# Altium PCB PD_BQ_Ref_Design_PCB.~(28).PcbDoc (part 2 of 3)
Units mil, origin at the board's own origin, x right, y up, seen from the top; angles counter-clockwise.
Board outline 2300 x 3400 mil, 4 copper layers (Top Layer, Signal Layer 1, Signal Layer 2, Bottom Layer), stack 61.2 mil thick; 124 components, 53 nets, 359 pads, 494 vias.
Unrouted connection lines stored in the file: 227.

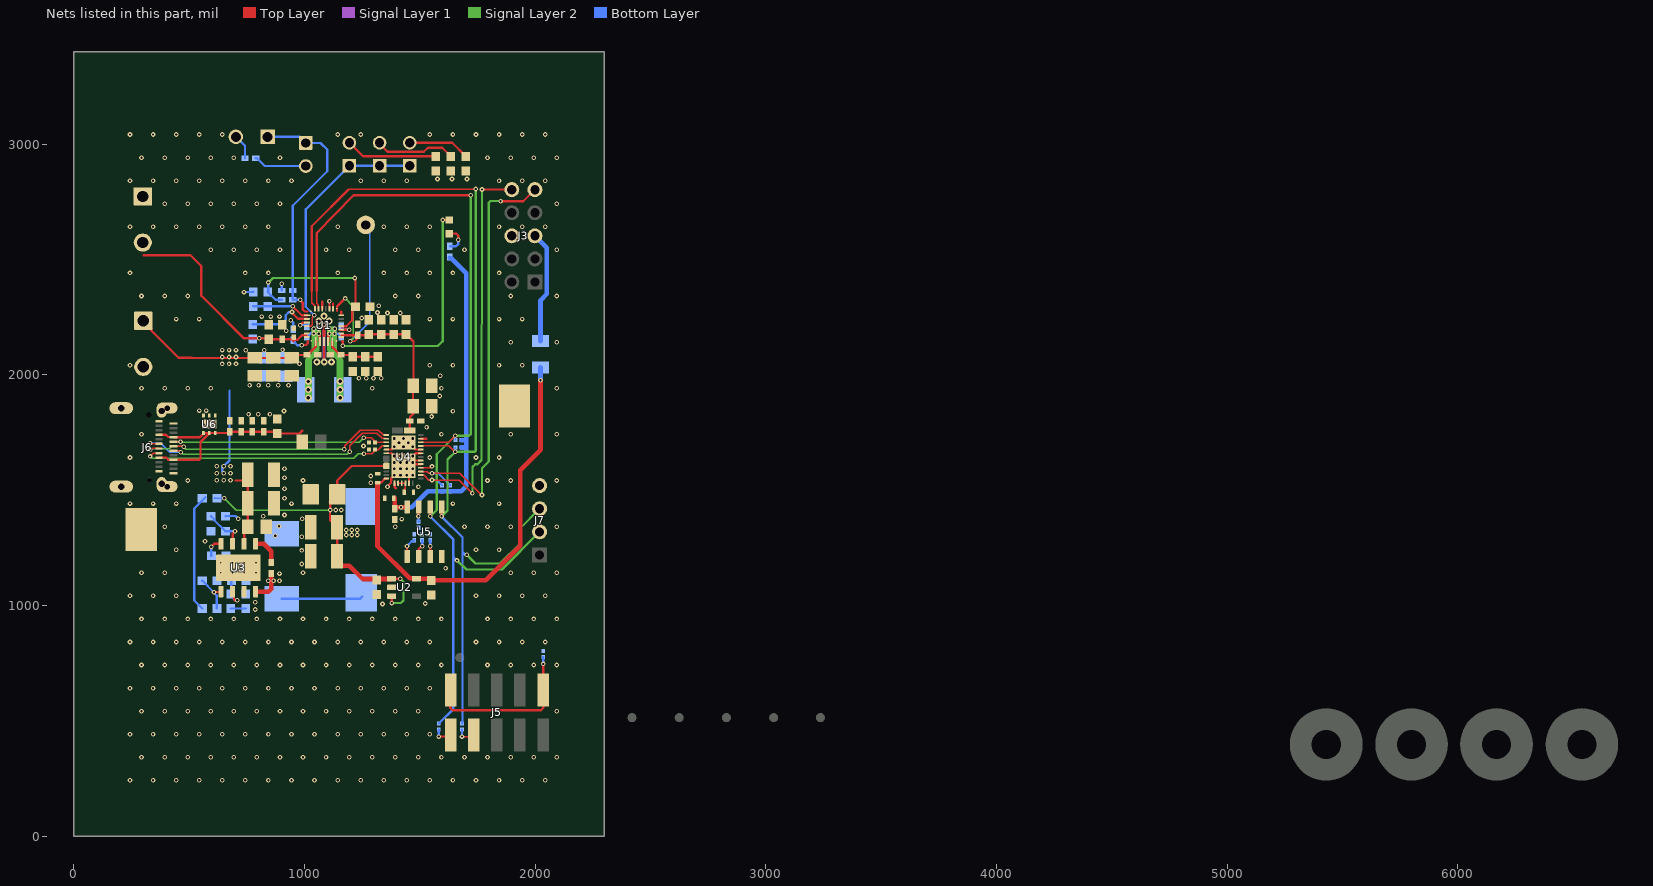
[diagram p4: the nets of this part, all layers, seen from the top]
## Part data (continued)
LOGO5: library part CMP-0074837-1, "IEC 61010-1 Hot Surface Warning"
NT1: library part CMP-0078142-3, "Single point connection between nets.", Manufacturer=N/A
R1: library part CMP-0022736-4, "RES, 100, 1%, 0.1 W, 0603", Manufacturer=Yageo, Power_W=100mW, Supplier Part Number 1=311-100HRCT-ND, TempCo="100 ppm/C", Tolerance_%=1%, Value2=0.1W, Value_Code=100R, ValueDisplayed=100
R2: library part CMP-0026232-2, "RES, 2.21 k, 1%, 0.063 W, AEC-Q200 Grade 0, 0402", Manufacturer=Vishay-Dale, Power_W=63mW, Supplier Part Number 1=541-2.21KLCT-ND, TempCo="100 ppm/C", Tolerance_%=1%, Value2=0.063W, Value_Code=2k21, ValueDisplayed=2.21k
R3: library part CMP-0026464-2, "RES, 5.23 k, 1%, 0.063 W, AEC-Q200 Grade 0, 0402", Manufacturer=Vishay-Dale, PartNumber=CRCW04025K23FKED, Power_W=63mW, Supplier Part Number 1=541-5.23KLCT-ND, TempCo="100 ppm/C", Tolerance_%=1%, Value2=0.063W, Value_Code=5k23, ValueDisplayed=5.23k
R4: library part CMP-0022788-4, "RES, 137 k, 1%, 0.1 W, 0603", Manufacturer=Yageo, Power_W=100mW, Supplier Part Number 1=311-137KHRCT-ND, TempCo="100 ppm/C", Tolerance_%=1%, Value2=0.1W, Value_Code=137k
R5: library part CMP-0026284-2, "RES, 30.1 k, 1%, 0.063 W, AEC-Q200 Grade 0, 0402", Manufacturer=Vishay-Dale, PartNumber=CRCW040230K1FKED, Power_W=63mW, Supplier Part Number 1=541-30.1KLCT-ND, TempCo="100 ppm/C", Tolerance_%=1%, Value2=0.063W, Value_Code=30k1, ValueDisplayed=30.1k
R6: library part CMP-0022735-5, "RES, 100 k, 1%, 0.1 W, 0603", Manufacturer=Yageo, Power_W=100mW, Supplier Part Number 1=311-100KHRCT-ND, TempCo="100 ppm/C", Tolerance_%=1%, Value2=0.1W, Value_Code=100k
R7: library part CMP-0025958-3, "RES, 10.0 k, 1%, 0.063 W, AEC-Q200 Grade 0, 0402", Manufacturer=Vishay-Dale, PartNumber=CRCW040210K0FKED, Power_W=63mW, Supplier Part Number 1=541-10.0KLCT-ND, TempCo="100 ppm/C", Tolerance_%=1%, Value2=0.063W, Value_Code=10k0, ValueDisplayed=10.0k
R8: library part CMP-0023246-5, "RES, 6.04 k, 1%, 0.1 W, 0603", Manufacturer=Yageo, Power_W=100mW, Supplier Part Number 1=311-6.04KHRCT-ND, TempCo="100 ppm/C", Tolerance_%=1%, Value2=0.1W, Value_Code=6k04, ValueDisplayed=6.04k
R9: library part CMP-0022000-4, "RES, 10.5 k, 1%, 0.1 W, AEC-Q200 Grade 0, 0603", Manufacturer=Vishay-Dale, Power_W=100mW, Supplier Part Number 1=541-10.5KHCT-ND, TempCo="100 ppm/C", Tolerance_%=1%, Value2=0.1W, Value_Code=10k5, ValueDisplayed=10.5k
R10: library part CMP-0022089-4, "RES, 17.4 k, 1%, 0.1 W, AEC-Q200 Grade 0, 0603", Manufacturer=Vishay-Dale, Power_W=100mW, Supplier Part Number 1=541-17.4KHCT-ND, TempCo="100 ppm/C", Tolerance_%=1%, Value2=0.1W, Value_Code=17k4, ValueDisplayed=17.4k
R11: library part CMP-0017299-3, "RES, 10.0, 1%, 0.25 W, AEC-Q200 Grade 0, 1206", Manufacturer=Panasonic, Power_W=250mW, Supplier Part Number 1=P10.0FCT-ND, TempCo="100 ppm/C", Tolerance_%=1%, Value2=0.25W, Value_Code=10R0, ValueDisplayed=10.0
R12: library part CMP-0022483-4, "RES, 51.1, 1%, 0.1 W, AEC-Q200 Grade 0, 0603", Manufacturer=Vishay-Dale, Power_W=100mW, Supplier Part Number 1=541-51.1HCT-ND, TempCo="100 ppm/C", Tolerance_%=1%, Value2=0.1W, Value_Code=51R1, ValueDisplayed=51.1
R13: library part CMP-0022546-4, "RES, 665 k, 1%, 0.1 W, AEC-Q200 Grade 0, 0603", Manufacturer=Vishay-Dale, Power_W=100mW, Supplier Part Number 1=541-665KHCT-ND, TempCo="100 ppm/C", Tolerance_%=1%, Value2=0.1W, Value_Code=665k
R14: library part CMP-0021999-4, "RES, 10.2 k, 1%, 0.1 W, AEC-Q200 Grade 0, 0603", Manufacturer=Vishay-Dale, Power_W=100mW, Supplier Part Number 1=541-10.2KHCT-ND, TempCo="100 ppm/C", Tolerance_%=1%, Value2=0.1W, Value_Code=10k2, ValueDisplayed=10.2k
R15: library part CMP-0022036-4, "RES, 130 k, 1%, 0.1 W, AEC-Q200 Grade 0, 0603", Manufacturer=Vishay-Dale, Power_W=100mW, Supplier Part Number 1=541-130KHCT-ND, TempCo="100 ppm/C", Tolerance_%=1%, Value2=0.1W, Value_Code=130k
R16: library part CMP-0022137-4, "RES, 1.96 k, 1%, 0.1 W, AEC-Q200 Grade 0, 0603", Manufacturer=Vishay-Dale, Power_W=100mW, Supplier Part Number 1=541-1.96KHCT-ND, TempCo="100 ppm/C", Tolerance_%=1%, Value2=0.1W, Value_Code=1k96, ValueDisplayed=1.96k
R17: library part CMP-0022360-4, "RES, 37.4 k, 1%, 0.1 W, AEC-Q200 Grade 0, 0603", Manufacturer=Vishay-Dale, Power_W=100mW, Supplier Part Number 1=541-37.4KHCT-ND, TempCo="100 ppm/C", Tolerance_%=1%, Value2=0.1W, Value_Code=37k4, ValueDisplayed=37.4k
R21 R22 R24 R25: library part CMP-0027272-3, "RES, 2.20 k, 1%, 0.05 W, 0201", Manufacturer=Vishay-Dale, Power_W=50mW, Supplier Part Number 1=541-2.20KAABCT-ND, TempCo="100 ppm/C", Tolerance_%=1%, Value2=0.05W, Value_Code=2k20, ValueDisplayed=2.20k
R26 R27 R29: library part CMP-0027008-4, "RES, 0, 5%, 0.05 W, 0201", Manufacturer=Vishay-Dale, Power_W=50mW, Supplier Part Number 1=72M6743, TempCo=ppm/C, Tolerance_%=5%, Value2=0.05W, Value_Code=0000, ValueDisplayed=0
R28 R30 R31 R32: library part CMP-0027262-3, "RES, 10.0 k, 1%, 0.05 W, 0201", Manufacturer=Vishay-Dale, Power_W=50mW, Supplier Part Number 1=541-10.0KAABCT-ND, TempCo="100 ppm/C", Tolerance_%=1%, Value2=0.05W, Value_Code=10k0, ValueDisplayed=10.0k
SH-J1 SH-J2: library part CMP-0003623-1, "Shunt, 100mil, Gold plated, Black", Alternate Manufacturer=3M, Alternate PartNumber=969102-0000-DA, Manufacturer=Samtec, Supplier Part Number 1=SNT-100-BK-G-ND
TP1: library part CMP-0055137-1, "Test Point, Miniature, Red, TH", Color=Red, Manufacturer=Keystone, Supplier Part Number 1=36-5000-ND
TP2 TP3: library part CMP-0055153-1, "Test Point, Compact, SMT", Manufacturer=Keystone, Supplier Part Number 1=36-5016TR-ND
U1: library part CMP-0088656-1, "BQ2579x HotRod", Manufacturer="Texas Instruments", Operating Temperature Range=to
U2: library part CMP-0074640-3, "500-mA, Low IQ, Small Size, Low Dropout Regulator, DBV0005A (SOT-23-5)", Alternate Manufacturer="Texas Instruments"
U3: library part CMP-0067056-2, "3.5V to 28V Input, 5A, 570kHz Step-Down Converter with Eco-mode, DDA0008E (SOIC-8)", Alternate Manufacturer="Texas Instruments", Alternate PartNumber=TPS54531DDA
U4: library part CMP-0090338-5, "USB Type-C and USB PD Controller with Integrated Power Switches Optimized for Power Applications", Manufacturer="Texas Instruments", Max Supply Voltage=22V, Min Supply Voltage=3V, Operating Temperature Range="-40°C to +125°C"
U5: library part CMP-0005314-2, "256 kb I2C CMOS Serial EEPROM, SOIC-8", Manufacturer="ON Semiconductor", Supplier Part Number 1=CAT24C256WI-G-ND
U6: library part CMP-0077834-1, "22-V Precision Surge Protection Clamp, DRV0006A (WSON-6)", Alternate Manufacturer="Texas Instruments"
ZZ1: library part CMP-0003616-3

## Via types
v1: diameter 20, hole 10, Top Layer to Bottom Layer, tented both sides, 445 vias
v2: diameter 23.62, hole 11.81, Top Layer to Bottom Layer, 24 vias
v3: diameter 30, hole 15, Top Layer to Bottom Layer, tented both sides, 12 vias
v4: diameter 19.68, hole 7.87, Top Layer to Bottom Layer, tented both sides, 10 vias
v5: diameter 20, hole 10, Top Layer to Bottom Layer, 3 vias

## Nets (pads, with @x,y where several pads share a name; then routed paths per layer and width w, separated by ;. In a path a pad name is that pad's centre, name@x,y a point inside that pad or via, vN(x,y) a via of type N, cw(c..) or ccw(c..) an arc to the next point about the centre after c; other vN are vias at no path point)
AGND: C22.2 J3.6 J4.2 NT1.2 R5.1 R6.1 R7.1 R8.1 R9.1 R10.1 U1.10 U1.11 U1.13 | length 298.5
  Top Layer w10: 1076.77,2316.93 1076.89,2316.81 U1.13@1076.89,2285.33 ; 1108.27,2307.09 1108.27,2285.45 U1.11@1108.39,2285.33 ; 1124.02,2309.06 1124.13,2308.94 U1.10@1124.13,2285.33
  Bottom Layer w10: J4.2@702.76,3031.5 742.13,2992.13 R7.1@742.13,2938.98 ; v1(738.19,2358.27) 776.76,2358.27 R6.1@777.74,2359.25 ; v1(901.57,2393.7) 901.57,2365.28 R5.1@901.69,2365.16 ; v1(940.94,2236.22) 951.89,2225.28 C22.2@951.89,2196.85
  other v1: 1108.27,2318.9 1576.77,2848.43 1639.76,2848.43 1704.72,2848.43
BAT: C19.1 C20.1 C21.1 J2.2 R1.1 U1.22 U1.23 | length 977.6
  Top Layer w10: 303.15,2518.11 505.51,2518.11 553.15,2470.47 553.15,2342.52 738.19,2157.48 v1(804.75,2157.48) 840.67,2157.48 C21.1@844.61,2153.54 C20.1@903.66,2153.54 946.97,2153.54 952.87,2147.64 ; 952.87,2145.67 952.87,2147.64 ; 1008.98,2171.26 989.29,2171.26 969.72,2151.69 956.93,2151.69 952.87,2147.64
  Bottom Layer w10: R1.1@775.59,2155.51 777.56,2153.54 781.5,2157.48 v1(804.75,2157.48)
C_CC1: C42.1 J6.A5 U4.28 | length 942.2
  Top Layer w6: J6.A5@432.09,1709.65 432.58,1709.15 462.11,1709.15 v1(462.6,1708.66) ; v1(1256.7,1726.38) 1289.27,1726.38 1306.3,1709.35 C42.1@1306.3,1706.69 1354.95,1706.69 U4.28@1355.13,1706.87
  Signal Layer 2 w6: v1(462.6,1708.66) 464.57,1706.69 1237.01,1706.69 v1(1256.7,1726.38)
C_CC2: C41.1 J6.B5 U4.29 | length 1095.8
  Top Layer w6: v1(330.71,1645.67) 345.47,1660.43 J6.B5@369.09,1660.43 ; v1(1257.87,1657.48) 1291.24,1657.48 1306.3,1672.54 C41.1@1306.3,1675.2 1320.87,1675.2 1336.8,1691.13 U4.29@1355.13,1691.13
  Signal Layer 2 w6: v1(330.71,1645.67) 333.35,1645.67 341.22,1637.8 1214.57,1637.8 1234.25,1657.48 v1(1257.87,1657.48)
C_USB_N: J6.A7 J6.B7 U4.27 | length 1182
  Top Layer w6: v1(330.71,1702.76) 333.66,1699.8 J6.B7@369.09,1699.8 ; J6.A7@432.09,1670.28 457.68,1670.28 v1(463.52,1664.43) ; v1(1196.85,1665.35) 1196.85,1692.91 1250.81,1746.87 1314.15,1746.87 1337.46,1723.56 1354.19,1723.56 U4.27@1355.13,1722.62
  Signal Layer 2 w6: v1(463.52,1664.43) 465.12,1664.43 474.04,1655.51 1186.34,1655.51 v1@1196.51,1665.69
  Bottom Layer w6: v1(330.71,1702.76) 377.95,1702.76 416.28,1664.43 v1(463.52,1664.43) ; v1@1196.18,1665.35 v1(1196.85,1665.35)
C_USB_P: J6.A6 J6.B6 U4.26 | length 1175.4
  Top Layer w6: v1(330.71,1674.76) 334.5,1674.76 339.86,1680.12 J6.B6@369.09,1680.12 ; J6.A6@432.09,1689.96 469.64,1689.96 472.59,1687.01 v1(476.38,1687.01) ; v1(1173.23,1677.17) 1173.77,1677.71 1173.77,1691.49 1242.13,1759.84 1320.87,1759.84 1341.4,1739.31 1354.19,1739.31 U4.26@1355.13,1738.37
  Signal Layer 2 w6: v1(330.71,1674.76) 334.5,1674.76 338.88,1679.13 413.39,1679.13 424.21,1689.96 465.86,1689.96 466.14,1689.69 473.7,1689.69 v1(476.38,1687.01) ; v1@474.9,1688.48 486.22,1677.17 v1(1173.23,1677.17)
GND: C2.1 C3.1 C4.1 C5.1 C6.2 C8.1 C9.1 C10.1 C11.2 C12.2 C13.2 C14.2 C15.2 C16.2 C17.2 C18.2 C19.2 C20.2 C21.2 C23.1 C24.1 C26.2 C27.2 C28.2 C29.2 C30.2 C31.2 C33.2 C34.2 C35.2 C36.2 C37.2 C38.2 C39.2 C40.2 C41.2 C42.2 C43.2 C44.2 C45.1 C46.1 C47.1 C48.1 D2.2 J1.2 J2.1 J6.A1 J6.A12 J6.B1 J6.B12 J6.S1 J6.S2 J6.S3 J6.S4 J7.4 NT1.1 R15.1 R16.1 R17.1 R28.1 R29.1 R30.1 R31.1 R32.1 TP2.1 TP3.1 U1.27 U2.2 U3.7 U3.9@713.58,1163.11 U4.5 U4.10 U4.11 U4.12 U4.14 U4.18 U4.31 U4.39 U5.4 U6.1 U6.2 U6.3 U6.7@587.6,1785.43 | length 894.8
  Top Layer w6: U4.10@1504.73,1596.64 1547.42,1596.64 v1(1553.15,1602.36)
  Top Layer w8: U4.31@1355.13,1659.63 1377.57,1659.63
  Top Layer w10: 1084.76,2171.26 U1.27@1084.76,2143.6 1084.76,2055.12 v3(1085.75,2055.12) ; v1(1360.24,1513.78) 1360.24,1516.49 1375.56,1531.81 1375.56,1541.09 1376.94,1542.47 1376.94,1551.52 1429.93,1604.51 U4.39@1429.93,1605.89 ; 1377.57,1659.63 U4.39@1429.93,1607.27 ; U4.39@1443.51,1592.31 U4.39@1429.93,1605.89 ; U4.39@1443.51,1619.47 U4.39@1429.93,1605.89 ; U4.39@1451.48,1628.82 1482.29,1659.63 U4.14@1504.73,1659.63 ; U4.39@1452.17,1628.13 U4.12@1504.73,1628.13 U4.39@1470.09,1628.13 ; U4.5@1453.55,1529.71 U4.39@1453.55,1582.27 ; U4.39@1470.09,1612.39 U4.11@1504.73,1612.39 ; U4.18@1504.73,1722.62 1527.74,1722.62
  Top Layer w15: 1084.76,2171.26 v1@1084.76,2216.72
  Signal Layer 1 w15: v1(1084.76,2216.75) 1084.88,2216.63 1084.88,2055.98 v3(1085.75,2055.12)
  other v1: 243.83,241.2 343.83,241.2 443.83,241.2 543.83,241.2 643.83,241.2 743.83,241.2 843.83,241.2 943.83,241.2 1043.83,241.2 1143.83,241.2 1243.83,241.2 1343.83,241.2 1443.83,241.2 1543.83,241.2 1643.83,241.2 1743.83,241.2 1843.83,241.2 1943.83,241.2 2043.83,241.2 293.83,341.2 393.83,341.2 493.83,341.2 593.83,341.2 693.83,341.2 793.83,341.2 893.83,341.2 993.83,341.2 1093.83,341.2 1193.83,341.2 1293.83,341.2 1393.83,341.2 1493.83,341.2 1593.83,341.2 1693.83,341.2 1793.83,341.2 1893.83,341.2 1993.83,341.2 2093.83,341.2 243.83,441.2 343.83,441.2 443.83,441.2 543.83,441.2 643.83,441.2 743.83,441.2 843.83,441.2 943.83,441.2 1043.83,441.2 1143.83,441.2 1243.83,441.2 1343.83,441.2 1443.83,441.2 1543.83,441.2 293.83,541.2 393.83,541.2 493.83,541.2 593.83,541.2 693.83,541.2 793.83,541.2 893.83,541.2 993.83,541.2 1093.83,541.2 1193.83,541.2 1293.83,541.2 1393.83,541.2 1493.83,541.2 2093.83,541.2 243.83,641.2 343.83,641.2 443.83,641.2 543.83,641.2 643.83,641.2 743.83,641.2 843.83,641.2 943.83,641.2 1043.83,641.2 1143.83,641.2 1243.83,641.2 1343.83,641.2 1443.83,641.2 1543.83,641.2 293.83,741.2 393.83,741.2 493.83,741.2 593.83,741.2 693.83,741.2 793.83,741.2 893.83,741.2 993.83,741.2 1093.83,741.2 1193.83,741.2 1293.83,741.2 1393.83,741.2 1493.83,741.2 1593.83,741.2 1793.83,741.2 1893.83,741.2 1993.83,741.2 2093.83,741.2 243.83,841.2 343.83,841.2 443.83,841.2 543.83,841.2 643.83,841.2 743.83,841.2 843.83,841.2 943.83,841.2 1043.83,841.2 1143.83,841.2 1243.83,841.2 1343.83,841.2 1443.83,841.2 1543.83,841.2 1743.83,841.2 1843.83,841.2 1943.83,841.2 2043.83,841.2 293.83,941.2 393.83,941.2 493.83,941.2 593.83,941.2 693.83,941.2 793.83,941.2 893.83,941.2 993.83,941.2 1093.83,941.2 1193.83,941.2 1293.83,941.2 1393.83,941.2 1493.83,941.2 1593.83,941.2 1793.83,941.2 1893.83,941.2 1993.83,941.2 2093.83,941.2 787.4,982.28 1338.58,1005.91 1523.31,1007.87 787.4,1013.78 243.83,1041.2 343.83,1041.2 443.83,1041.2 1743.83,1041.2 1843.83,1041.2 1943.83,1041.2 2043.83,1041.2 293.83,1141.2 393.83,1141.2 993.83,1141.2 1893.83,1141.2 1993.83,1141.2 2093.83,1141.2 1611.89,1161.42 988.19,1179.13 988.19,1238.19 443.83,1241.2 1743.83,1241.2 1843.83,1241.2 568.9,1277.56 988.19,1297.24 874.02,1301.18 393.83,1341.2 1393.83,1341.2 1693.83,1341.2 1793.83,1341.2 1893.83,1341.2 2093.83,1341.2 889.76,1342.52 1421.26,1374.02 990.16,1375.98 820.87,1385.83 913.39,1391.73 243.83,1441.2 343.83,1441.2 443.83,1441.2 943.83,1441.2 1643.83,1441.2 1843.83,1441.2 913.39,1464.57 913.39,1505.91 1494.09,1513.78 1287.4,1531.5 493.83,1541.2 993.83,1541.2 1793.83,1541.2 1893.83,1541.2 2093.83,1541.2 913.39,1553.15 1287.4,1561.02 913.39,1592.52 243.83,1641.2 1543.83,1641.2 1743.83,1641.2 1843.83,1641.2 1255.91,1690.94 293.83,1741.2 1593.83,1741.2 1893.83,1741.2 2093.83,1741.2 1529.53,1771.65 1551.18,1818.9 757.87,1828.74 799.21,1828.74 850.39,1828.74 1643.83,1841.2 911.42,1842.52 543.31,1844.49 574.8,1844.49 1586.61,1907.48 293.83,1941.2 393.83,1941.2 493.83,1941.2 593.83,1941.2 1293.83,1941.2 1593.83,1941.2 2093.83,1941.2 762.09,1954.72 801.18,1954.72 842.52,1954.72 885.83,1954.72 931.1,1954.72 1236.22,1984.25 1267.72,1984.25 1299.21,1984.25 1332.68,1984.25 1588.58,1996.06 243.83,2041.2 1543.83,2041.2 1643.83,2041.2 1843.83,2041.2 1943.83,2041.2 1893.83,2141.2 2093.83,2141.2 921.26,2190.94 443.83,2241.2 543.83,2241.2 1543.83,2241.2 1643.83,2241.2 1843.83,2241.2 1943.83,2241.2 1248.03,2246.06 814.96,2251.97 854.33,2251.97 891.73,2251.97 1360.24,2267.72 1415.35,2267.72 1316.93,2269.69 1322.83,2299.21 293.83,2341.2 393.83,2341.2 493.83,2341.2 1393.83,2341.2 1493.83,2341.2 1893.83,2341.2 2093.83,2341.2 243.83,2441.2 743.83,2441.2 843.83,2441.2 1143.83,2441.2 1343.83,2441.2 1443.83,2441.2 1543.83,2441.2 1643.83,2441.2 1843.83,2441.2 593.83,2541.2 693.83,2541.2 793.83,2541.2 893.83,2541.2 1093.83,2541.2 1193.83,2541.2 1393.83,2541.2 1493.83,2541.2 1693.83,2541.2 2093.83,2541.2 243.83,2641.2 343.83,2641.2 443.83,2641.2 543.83,2641.2 643.83,2641.2 743.83,2641.2 843.83,2641.2 1143.83,2641.2 1343.83,2641.2 1443.83,2641.2 1543.83,2641.2 1843.83,2641.2 1943.83,2641.2 2043.83,2641.2 393.83,2741.2 493.83,2741.2 593.83,2741.2 693.83,2741.2 793.83,2741.2 893.83,2741.2 2093.83,2741.2 243.83,2841.2 343.83,2841.2 443.83,2841.2 543.83,2841.2 643.83,2841.2 743.83,2841.2 843.83,2841.2 943.83,2841.2 1243.83,2841.2 1343.83,2841.2 1443.83,2841.2 1843.83,2841.2 1943.83,2841.2 2043.83,2841.2 293.83,2941.2 393.83,2941.2 493.83,2941.2 593.83,2941.2 693.83,2941.2 893.83,2941.2 1793.83,2941.2 1893.83,2941.2 1993.83,2941.2 2093.83,2941.2 243.83,3041.2 343.83,3041.2 443.83,3041.2 543.83,3041.2 643.83,3041.2 1143.83,3041.2 1243.83,3041.2 1543.83,3041.2 1643.83,3041.2 1743.83,3041.2 1843.83,3041.2 1943.83,3041.2 2043.83,3041.2
  other v2: 1389.77,1564.55 1416.54,1564.55 1443.32,1564.55 1470.09,1564.55 1389.77,1592.11 1416.54,1592.11 1443.32,1592.11 1470.09,1592.11 1389.77,1619.67 1416.54,1619.67 1443.32,1619.67 1470.09,1619.67 1389.77,1647.23 1416.54,1647.23 1443.32,1647.23 1470.09,1647.23
  other v3: 1054.25,2055.12 1117.24,2055.12 1062.11,2232.27 1107.4,2232.28 1084.75,2254.14
  other v4: 636.81,1141.46 687.99,1141.46 739.17,1141.46 790.35,1141.46 636.81,1184.76 687.99,1184.76 739.17,1184.76 790.35,1184.76 565.94,1785.43 609.25,1785.43
I2C1_SCL: J3.9 R21.1 U4.9 | length 1911.4
  Top Layer w6: U4.9@1504.73,1580.89 1505.67,1579.95 1532.36,1579.95 1539.48,1572.83 v1(1553.15,1572.83) 1673.23,1572.83 1768.7,1477.36 v5@1769.69,1476.38
  Top Layer w10: v5(1850.39,2751.97) 1948.82,2751.97 J3.9@1999.02,2802.17
  Signal Layer 2 w10: v5(1769.69,1478.35) 1769.69,1594.08 1799.21,1623.61 1799.21,2744.84 1807.09,2752.72 1849.65,2752.72 v5(1850.39,2751.97)
  Bottom Layer w10: v1(1553.15,1572.83) 1579.92,1572.83 R21.1@1631.89,1520.87
I2C1_SDA: J3.10 R22.1 U4.8 | length 1783.2
  Top Layer w6: U4.8@1504.73,1565.14 1505.67,1564.2 1518.47,1564.2 1539.37,1543.31 v1(1553.15,1543.31) 1671.26,1543.31 v1(1728.35,1486.22) v1@1728.35,1484.25
  Top Layer w10: v5(1769.69,2803.15) J3.10@1899.02,2802.17
  Signal Layer 2 w10: v1(1728.35,1486.22) 1728.35,1600.39 1740.16,1612.2 1750,1612.2 1767.72,1629.92 1769.69,2805.12 v5(1769.69,2803.15)
  Bottom Layer w10: v1(1553.15,1543.31) 1574.02,1543.31 R22.1@1596.46,1520.87
I2C_SCL: J7.2 R24.2 R26.1 U1.14 U4.17 U5.6 | length 4218
  Top Layer w6: 1053.15,2364.17 1053.15,2309.06 1060.2,2302 1060.2,2286.27 U1.14@1061.14,2285.33 ; U4.17@1504.73,1706.87 1624.95,1706.87 v1(1653.54,1735.47)
  Top Layer w10: 1053.15,2364.17 1053.15,2614.17 1212.6,2777.56 v1(1720.47,2777.56) ; v1(1545.28,1385.83) U5.6@1545.28,1426.7
  Signal Layer 2 w10: v1(1545.28,1385.83) 1573.15,1413.7 1573.15,1655.08 v1(1653.54,1735.47) 1713.82,1735.47 1720.47,1742.13 v1(1720.47,2777.56) ; v1(1661.42,1194.88) 1702.76,1155.51 1856.3,1155.51 J7.2@2019.69,1318.9
  Bottom Layer w6: v1(1653.54,1735.47) 1653.54,1717.32 R24.2@1654.33,1716.54
  Bottom Layer w10: v1(1545.28,1385.83) 1645.67,1285.43 1645.67,1208.66 ; R26.1@1582.68,487.4 1582.68,488.19 1585.94,491.46 1586.03,491.46 1645.67,551.09 1645.67,1208.66 ; v1(1661.42,1194.88) 1647.64,1208.66 1645.67,1208.66
I2C_SDA: J7.3 R25.2 R27.1 U1.15 U4.16 U5.5 | length 4321.3
  Top Layer w6: 1031.5,2364.17 1031.5,2311.02 1044.46,2298.06 1044.46,2286.27 U1.15@1045.39,2285.33 ; U4.16@1504.73,1691.13 1625.8,1691.13 1651.58,1665.35 v1(1653.54,1665.35)
  Top Layer w10: 1031.5,2364.17 1031.5,2643.7 1190.94,2803.15 ; 1188.98,2803.15 v1@1740.16,2805.12 ; v1(1594.49,1385.83) U5.5@1594.49,1426.7
  Signal Layer 2 w10: v1(1594.49,1385.83) 1620.08,1411.42 1620.08,1631.89 v1(1653.54,1665.35) 1738.19,1665.35 1742.13,1669.29 v1(1742.13,2805.12) ; v1(1704.33,1218.9) 1742.13,1181.1 1848.43,1181.1 1933.07,1265.75 1933.07,1332.28 J7.3@2019.69,1418.9
  Bottom Layer w6: v1(1653.54,1665.35) 1653.54,1684.25 R25.2@1654.33,1685.04
  Bottom Layer w10: v1(1594.49,1385.83) 1685.04,1295.28 1685.04,1232.28 ; R27.1@1683.07,487.4 1685.04,489.37 1685.04,1232.28 ; v1(1704.33,1218.9) 1698.43,1218.9 1685.04,1232.28
ILIM_HIZ: R4.1 R6.2 U1.17 | length 250.9
  Top Layer w10: v1(948.82,2297.24) 988.28,2257.77 U1.17@1011.93,2257.77
  Bottom Layer w10: R6.2@777.74,2296.26 778.73,2297.24 938.5,2297.24 v1(948.82,2297.24)
LDO_1V5: C37.1 U4.2 U4.3 U4.4 | length 83
  Top Layer w6: U4.2@1406.31,1529.71 U4.3@1422.06,1529.71 U4.4@1437.8,1529.71 1437.8,1508.67 1433.07,1503.94 1433.07,1480.63 C37.1@1432.76,1480.32
LDO_3V3: C36.1 C43.1 R2.2 R21.2 R22.2 R24.1 R25.1 U4.1 U5.8 | length 1507.2
  Top Layer w10: U4.1@1390.56,1529.71 1391.62,1528.65 1391.62,1511.92 1395.67,1507.87
  Top Layer w20: C43.1@1391.73,1419.29 1391.73,1423.23 C43.1@1393.54,1425.04 ; C36.1@1391.73,1465.4 1391.73,1425.04 C43.1@1393.54,1425.04 ; U5.8@1444.88,1427.09 1443.62,1425.83 v1(1418.59,1425.83) 1417.96,1425.2 1405.26,1425.2 1405.1,1425.04 C43.1@1393.54,1425.04
  Bottom Layer w20: v1@1419.29,1425.83 1465.2,1425.83 1534.25,1494.88 1604.33,1494.88 1633.86,1494.88 1663.39,1494.88 1679.92,1494.88 1700.79,1515.75 1700.79,1684.54 ; R2.2@1629.92,2506.89 1632.72,2504.09 1635.67,2504.09 1700.79,2438.98 1700.79,1717.11 ; R25.1@1680.31,1685.04 1680.81,1684.54 1700.79,1684.54 ; R24.1@1680.31,1716.54 1700.21,1716.54 1700.79,1717.11 ; 1700.79,1684.54 1700.79,1717.11
NetC1_1: C1.1 U1.4 | length 76.9
  Top Layer w10: U1.4@1159.57,2194.78 1193.92,2194.78 v1(1194.02,2194.88)
  Bottom Layer w10: C1.1@1160.55,2210.63 1160.55,2206.69 1172.46,2194.78 1193.92,2194.78 v1(1194.02,2194.88)
NetC1_2: C1.2 L1.1 U1.28 | length 640.5
  Top Layer w10: U1.28@1102.48,2143.6 1103.54,2144.66 1103.54,2172.44 v1(1108.27,2177.17)
  Signal Layer 2 w20: 1154.65,2061.02 1130.25,2085.42 ; v1(1108.27,2177.17) 1108.27,2197.95 v1(1107.4,2198.82) v1(1131.02,2198.82) 1129.92,2197.72 v1(1129.92,2177.17) ; v1(1108.27,2177.17) v1(1129.92,2177.17) ; v1(1108.27,2177.17) 1108.27,2109.17 1107.38,2108.29 1130.25,2085.42 ; v1(1129.92,2177.17) 1130.25,2176.84 1130.25,2085.42
  Signal Layer 2 w30: v3(1154.65,1899.61) 1154.65,2061.02
  Bottom Layer w10: v1(1129.92,2177.17) 1146.77,2177.17 C1.2@1160.55,2163.39
  Bottom Layer w20: v1@1107.4,2178.93 1108.27,2178.07 v1(1108.27,2177.17) v1(1129.92,2177.17) 1129.92,2197.72 v1(1131.02,2198.82) v1(1107.4,2198.82) v1@1107.4,2178.93
  other v3: 1154.65,1935.04 1154.65,1970.64
NetC7_1: C7.1 U1.19 | length 77
  Top Layer w10: v1(981.42,2214.57) 993.13,2226.28 U1.19@1011.54,2226.28
  Bottom Layer w10: v1(981.42,2214.57) 982.92,2216.07 1005.5,2216.07 C7.1@1010.94,2210.63 ; C7.1@1006.18,2214.57 C7.1@1012.99,2221.38
NetC7_2: C7.2 L1.2 U1.26 | length 624.4
  Top Layer w10: v1(1062.13,2177.73) 1062.13,2176.43 1065.98,2172.57 1065.98,2144.66 U1.26@1067.05,2143.6
  Signal Layer 2 w20: 1016.85,2062.24 1040.47,2085.86 v1(1040.47,2178.56) 1061.3,2178.56 v1(1062.13,2177.73) ; 1040.47,2092.52 1054.25,2106.3 1054.25,2169.86 v1(1062.13,2177.73) ; v1@1040.47,2179.54 v1(1040.47,2198.82) v1(1062.13,2198.82) v1(1062.13,2177.73)
  Signal Layer 2 w30: v3(1016.85,1899.61) v3(1016.85,1935.04) v3(1016.85,1970.5) 1016.85,2062.24
  Bottom Layer w10: C7.2@1010.94,2163.39 1026.69,2179.13 1027.27,2178.56 v1(1040.47,2178.56)
  Bottom Layer w20: v1(1040.47,2178.56) 1061.3,2178.56 v1(1062.13,2177.73) v1(1062.13,2198.82) v1(1040.47,2198.82) v1(1040.47,2178.56)
NetC22_1: C22.1 U1.24 | length 87.7
  Top Layer w10: v1(988.19,2127.95) 988.84,2128.6 1006.55,2128.6 1014.73,2136.78 1014.73,2144.71 1013.78,2145.67
  Bottom Layer w10: C22.1@951.89,2149.61 958.7,2142.8 958.7,2137.75 968.5,2127.95 v1(988.19,2127.95)
NetC25_1: C25.1 U3.1 | length 129.4
  Top Layer w20: U3.1@788.58,1266.46 824.09,1266.46 855.57,1234.98 C25.1@855.57,1185.58
NetC25_2: C25.2 D2.1 L2.1 U3.8 | length 493.1
  Top Layer w20: U3.8@788.58,1059.76 788.7,1059.76 789.41,1059.06 843.85,1059.06 855.57,1070.77 C25.2@855.57,1138.33
  Bottom Layer w10: D2.1@901.57,1028.8 1241.4,1028.8 L2.1@1250.98,1038.39
  other v1: 842.52,1106.3 866.14,1106.3 891.73,1106.3 891.73,1137.8
NetC32_1: C32.1 C34.1 U3.6 | length 164.6
  Top Layer w10: U3.6@688.58,1059.76 694.41,1053.94 694.41,1026.06 698.82,1021.65 v1(708.66,1021.65)
  Bottom Layer w10: C32.1@682.61,1049.21 C32.1@682.61,1047.75 ; C34.1@683.07,1106.3 683.07,1051.18 C32.1@681.1,1049.21 C32.1@682.61,1047.75 ; C32.1@683.81,1039.6 685.33,1045.12 C32.1@682.61,1047.75 ; v1(708.66,1021.65) 700.89,1021.65 682.61,1039.93 C32.1@682.61,1047.75
NetC32_2: C32.2 R17.2 | length 65.9
  Bottom Layer w10: C32.2@681.1,986.22 R17.2@747.05,986.22
NetC33_1: C33.1 U3.4 | length 86.7
  Top Layer w10: v1(596.46,1253.94) 608.98,1266.46 U3.4@638.58,1266.46
  Bottom Layer w10: C33.1@596.46,1214.57 v1(596.46,1253.94)
NetC44_1: C44.1 C45.2 C46.2 C47.2 C48.2 J6.A4 J6.A9 J6.B4 J6.B9 L3.1 U6.4 U6.5 U6.6 | length 961.1
  Top Layer w10: J6.B4@369.09,1640.75 399.84,1640.75 409.37,1631.22 431.77,1631.22 J6.A9@432.09,1630.91 447.21,1630.91 543.35,1630.91 549.21,1636.76 549.21,1708.66 583.74,1743.19 586.69,1743.19 587.6,1744.09 U6.5@587.6,1747.05 ; J6.B9@369.09,1739.17 399.84,1739.17 409.37,1729.65 431.77,1729.65 J6.A4@432.09,1729.33 547.24,1729.33 562.01,1744.09 U6.4@562.01,1747.05 583.74,1747.05 U6.5@587.6,1747.05 ; 991.5,1757.87 978.7,1745.08 C44.1@882.87,1745.08 875,1752.95 C48.2@823.82,1752.95 C47.2@774.61,1752.95 C46.2@725.39,1752.95 C45.2@676.18,1752.95 670.28,1747.05 U6.6@613.19,1747.05 U6.5@587.6,1747.05
NetD1_1: D1.1 R2.1 | length 119.8
  Top Layer w10: D1.1@1627.95,2611.22 1628.94,2612.2 1657.48,2612.2 1667.32,2602.36 v1(1667.32,2584.65)
  Bottom Layer w10: R2.1@1630.91,2557.09 1657.48,2557.09 1667.32,2566.93 v1(1667.32,2584.65)
NetJ3_5: J3.5 R11.1 | length 489.2
  Bottom Layer w20: J3.5@1999.02,2602.17 2050.83,2550.35 2050.83,2350.04 2023.62,2322.83 R11.1@2023.62,2145.67
NetJ5_1: J5.1 R26.2 | length 85
  Top Layer w10: v1(1582.68,431.1) 1627.5,431.1 J5.1@1634.47,438.07
  Bottom Layer w10: v1(1582.68,431.1) R26.2@1582.68,461.42
NetJ5_2: J5.2 J5.10 R29.2 | length 712.5
  Top Layer w10: J5.2@1634.47,632.95 1631.99,630.47 1631.99,555.02 1641.73,545.28 2025.59,545.28 2035.34,555.02 2035.34,632.08 J5.10@2034.47,632.95 2035.43,633.92 v1(2035.43,746.06)
  Bottom Layer w10: v1(2035.43,746.06) R29.2@2035.43,776.38
NetJ5_3: J5.3 R27.2 | length 84.6
  Top Layer w6: v1(1683.07,431.1) 1727.5,431.1 J5.3@1734.47,438.07
  Bottom Layer w10: v1(1683.07,431.1) R27.2@1683.07,461.42
NetJP1_2: JP1.2 R8.2 | length 398.4
  Top Layer w10: JP1.2@1194.88,3005.71 1253.74,2946.85 R8.2@1568.9,2946.85
NetJP2_2: JP2.2 R9.2 | length 350.8
  Top Layer w10: JP2.2@1325.79,3005.71 1325.79,3000.98 1360.59,2966.18 1517.56,2966.18 1535.63,2984.25 1597.44,2984.25 1633.86,2947.83 R9.2@1633.86,2946.85
NetJP3_2: JP3.2 R10.2 | length 267.1
  Top Layer w10: JP3.2@1456.69,3005.71 1640.94,3005.71 1698.82,2947.83 R10.2@1698.82,2946.85
NetJP4_2: JP4.2 R7.2 | length 230.7
  Bottom Layer w10: R7.2@789.37,2938.98 793.31,2938.98 827.56,2904.72 JP4.2@1005.91,2904.72
NetR1_2: R1.2 U1.18 | length 281.9
  Top Layer w10: v1(945.98,2271.65) 945.98,2268.58 971.79,2242.77 1010.2,2242.77 U1.18@1010.94,2242.03
  Bottom Layer w10: R1.2@775.59,2218.5 897.64,2218.5 919.29,2240.16 919.29,2257.77 919.24,2257.82 933.07,2271.65 v1(945.98,2271.65)
NetR12_1: R12.1 R14.2 | length 516.5
  Bottom Layer w10: R14.2@557.09,986.22 522.64,1020.67 522.64,1420.28 R12.1@570.87,1468.5
NetR13_1: R13.1 R15.2 U3.3 | length 192.6
  Top Layer w10: U3.3@688.58,1266.46 688.58,1310.63 v1(698.82,1320.87)
  Bottom Layer w10: R13.1@594.49,1386.81 595.47,1386.81 609.17,1373.11 609.17,1369.17 656.5,1321.85 R15.2@657.48,1321.85 658.46,1320.87 v1(698.82,1320.87)
NetR14_1: R14.1 R16.2 U3.5 | length 179
  Top Layer w10: v1(607.77,1057.09) 608.65,1057.96 636.78,1057.96 U3.5@638.58,1059.76
  Bottom Layer w10: R16.2@557.09,1106.3 558.07,1106.3 607.28,1057.09 v1(607.77,1057.09) 607.77,1054.38 620.08,1042.08 R14.1@620.08,986.22
NetR28_2: R28.2 U5.C | length 66
  Top Layer w10: v1@1494.49,1386.22 v1(1494.09,1385.83) 1494.09,1426.3 U5.C@1494.88,1427.09
  Bottom Layer w10: v1(1494.09,1385.83) 1494.59,1385.33 1494.59,1362.89 R28.2@1495.08,1362.4
NetR30_2: R30.2 U5.1 | length 87.4
  Top Layer w10: U5.1@1444.88,1212.52 v1(1444.88,1255.91)
  Bottom Layer w10: v1(1444.88,1255.91) 1444.88,1257.87 1465.24,1278.23 1473.11,1278.23 1476.38,1281.5 R30.2@1476.38,1282.28
NetR31_2: R31.2 U5.2 | length 76.5
  Top Layer w10: U5.2@1494.88,1212.52 1496.06,1213.71 1496.06,1244.09 1508.86,1256.89 v1(1510.83,1256.89)
  Bottom Layer w10: v1@1510.33,1257.38 R31.2@1510.33,1281.79
NetR32_2: R32.2 U5.3 | length 69.9
  Top Layer w10: U5.3@1544.88,1212.52 1544.97,1212.61 1544.97,1255.62 v1(1545.06,1255.71)
  Bottom Layer w10: v1(1545.06,1255.71) 1545.17,1255.81 1545.17,1282.18 R32.2@1545.28,1282.28
NetU4_15: U4.15 U4.30 U4.40 | length 233.7
  Top Layer w10: U4.30@1355.13,1675.38 1377.96,1675.38 U4.40@1407.88,1705.3 ; U4.40@1389.97,1687.39 U4.40@1407.88,1705.3 ; U4.15@1504.73,1675.38 1481.9,1675.38 ; U4.40@1407.88,1705.3 v2(1409.85,1705.3) U4.40@1429.93,1705.3 v2(1450.01,1705.3) 1451.98,1705.3 1481.9,1675.38 ; 1481.9,1675.38 1469.89,1687.39 1481.9,1675.38
  other v2: 1389.77,1687.58 1429.93,1687.58 1470.09,1687.58 1389.77,1723.02 1429.93,1723.02 1470.09,1723.02
P3V3: C24.2 C35.1 R11.2 U2.5 U4.38 | length 1869
  Top Layer w10: C35.1@1316.93,1531.18 1319.43,1533.68 1333.67,1533.68 1349.38,1549.39 U4.38@1355.13,1549.39
  Top Layer w20: C35.1@1316.93,1529.53 1316.93,1255.91 1455.77,1117.06 1484.41,1117.06 U2.5@1486.22,1115.25 ; U2.5@1488.03,1115.25 1542.49,1115.25 C24.2@1549.38,1108.36 1785.53,1108.36 1935.04,1257.87 1935.04,1586.61 2023.62,1675.2 v1(2023.62,1976.38)
  Bottom Layer w20: v1(2023.62,1976.38) R11.2@2023.62,2031.5
PMID: C8.2 C9.2 C10.2 C11.1 U1.29 | length 238.5
  Top Layer w10: U1.29@1120.2,2142.62 1121.1,2141.71 1121.1,2120.16 1147.83,2093.43 1147.83,2091.46 1153.66,2085.63 1200.91,2085.63 C10.2@1208.78,2077.76 C9.2@1263.9,2077.76 C8.2@1318.03,2077.76
PP5V: C23.2 C26.1 C27.1 C28.1 L2.2 R12.2 U2.1 U2.3 U4.34 U4.35 U4.@1355.13,1604.51 | length 1669.2
  Top Layer w10: C28.1@1141.73,1213.58 1142.13,1213.98 1142.13,1338.58 1111.14,1369.57 1111.14,1412.32 v1(1112.2,1413.39) 1112.2,1443.5 1108.27,1447.44 C26.1@1142.13,1481.3 ; C26.1@1158.86,1464.57 C26.1@1142.13,1481.3 ; U4.@1355.13,1604.51 1204.91,1604.51 1142.13,1541.73 C26.1@1142.13,1481.3 ; v1(1377.95,1009.84) U2.3@1377.95,1040.45 ; U2.1@1377.95,1115.25 1378.12,1115.42 1415.82,1115.42 v1(1415.99,1115.59)
  Top Layer w20: C28.1@1141.73,1213.58 1141.73,1186.85 1157.32,1171.26 1194.88,1171.26 1251.97,1114.17 1309.15,1114.17 C23.2@1313.98,1109.35 1318.8,1114.17 1376.87,1114.17 U2.1@1377.95,1115.25
  Signal Layer 2 w6: v1(652.78,1464.57) 703.97,1413.39 v1(1112.2,1413.39)
  Signal Layer 2 w10: v1(1377.95,1009.84) 1417.32,1009.84 1429.13,1021.65 1429.13,1102.36 1415.99,1115.51 v1(1415.99,1115.59)
  Bottom Layer w6: R12.2@608.27,1466.54 610.24,1464.57 612.2,1466.54 614.17,1464.57 v1(652.78,1464.57)
  other v1: 1181.1,1305.12 1204.72,1305.12 1228.35,1305.12 1181.1,1326.77 1204.72,1326.77 1228.35,1326.77 1135.83,1413.39 1159.45,1413.39
PPHV: C2.2 C3.2 C4.2 C5.2 C6.1 C38.1 C39.1 C40.1 TP1.1 U1.2 U1.3 U1.8 U1.9 U4.20 U4.21 U4.22 U4.@1456.56,1758.05 | length 1633.6
  Top Layer w6: 1158.58,2273.62 1159.57,2272.64 ; U1.2@1159.57,2163.29 1159.57,2171.26 U1.3@1159.57,2179.03 ; v1(1198.82,2145.67) 1218.62,2145.67 1237.32,2164.37 C6.1@1230.43,2171.26
  Top Layer w10: 1140.87,2276.6 1140.87,2295.28 ; U1.9@1140.87,2286.81 1140.87,2295.28 ; U1.8@1159.57,2259.84 1159.57,2272.64 ; 1162.52,2171.26 1185.42,2171.26 1185.73,2170.94 1202.3,2170.94 1202.61,2171.26 C6.1@1230.43,2171.26 1274.72,2171.26 C5.2@1278.66,2175.2 C4.2@1332.8,2175.2 C3.2@1386.93,2175.2 1441.06,2175.2 1472.61,2143.65 1472.61,1974.33 1470.8,1972.53 1470.8,1887.56 1472.61,1885.75 1471.09,1884.24 1471.09,1829.36 1457.89,1816.15 1457.89,1796.52 1456.56,1795.2 U4.@1456.56,1758.05 ; v1(1176.3,2330.71) 1140.87,2295.28
  Signal Layer 2 w6: v1(1176.3,2330.71) 1212.02,2294.99 1212.02,2158.87 v1(1198.82,2145.67)
  Bottom Layer w6: v1(1198.82,2145.67) 1283.46,2230.32 1283.46,2611.87 1265.75,2629.58 TP1.1@1265.75,2649.61
PROG: JP1.1 JP2.1 JP3.1 U1.20 | length 1073.5
  Top Layer w6: U1.20@1009.96,2210.53 1026.73,2210.53 1033.22,2217.02 1033.22,2247.36 1042.27,2256.41 v1(1042.27,2258.04)
  Bottom Layer w10: v1(1042.27,2258.04) 1005.91,2294.41 1005.91,2716.73 JP1.1@1194.88,2905.71 JP2.1@1325.79,2905.71 JP3.1@1456.69,2905.71
REGN: C18.1 R3.2 R4.2 U1.5 | length 752.8
  Top Layer w10: U1.5@1159.57,2210.53 1181.23,2210.53 1206.89,2236.19 1206.89,2280.59 1220.59,2294.29 C18.1@1221.57,2294.29 1221.57,2416.22 v1(1218.5,2419.29)
  Signal Layer 2 w10: v1(842.52,2399.61) 844.49,2399.61 864.17,2419.29 v1(1218.5,2419.29)
  Bottom Layer w10: R4.2@840.6,2359.25 R4.2@840.6,2358.27 ; v1(842.52,2399.61) 842.52,2364.12 844.49,2362.15 R4.2@840.6,2358.27 ; R3.2@901.69,2324.8 875.12,2324.8 855.35,2344.57 854.3,2344.57 R4.2@840.6,2358.27
STAT: D1.2 U1.1 | length 1022.6
  Top Layer w10: 1164.55,2145.6 1166.47,2143.69 v1(1166.47,2126.02) ; v1(1599.76,2670.62) 1624.65,2670.62 D1.2@1627.95,2667.32
  Signal Layer 2 w10: v1(1166.47,2126.02) 1168.38,2124.11 1175.46,2124.11 1175.55,2124.02 1578.15,2124.02 1599.76,2145.62 v1@1599.76,2675.2
SYS: C12.1 C13.1 C14.1 C15.1 C16.1 C17.1 C29.1 C30.1 C31.1 J1.1 R13.2 U1.25 U3.2 | length 1655.4
  Top Layer w10: J1.1@301.18,2233.86 335.55,2199.49 335.55,2192.01 454.72,2072.83 511.91,2072.83 512.26,2072.48 629.05,2072.48 643.23,2072.48 673.23,2072.48 v1@709.76,2072.48 ; 700.79,1541.34 C29.1@753.94,1541.34 ; v1@703.23,2072.48 v1@709.76,2072.48 ; U3.2@738.58,1266.46 738.58,1325.72 C31.1@754.11,1341.24 753.94,1341.41 C30.1@753.94,1442.91 ; C30.1@750,1446.85 C30.1@753.94,1442.91 ; C29.1@753.94,1566.93 C29.1@753.94,1541.34 ; U1.25@1049.33,2143.6 1048.43,2142.7 1048.43,2120.16 1024.65,2096.38 1013.9,2085.63 963.07,2085.63 949.92,2072.48 869.21,2072.48 789.49,2072.48 v1@709.76,2072.48 ; C30.1@753.94,1442.91 C29.1@753.94,1541.34
  Bottom Layer w10: 643.83,1581.2 v1@643.83,1602.83 ; v1(649.61,1602.83) 675.2,1628.43 675.2,1931.28 ; R13.2@657.48,1386.81 658.46,1387.8 700.79,1387.8 v1(712.6,1375.98)
  other v1: 619.61,1542.83 649.61,1542.83 679.61,1542.83 619.61,1572.83 649.61,1572.83 679.61,1572.83 619.61,1602.83 679.61,1602.83 643.23,2046.77 673.23,2046.77 703.23,2046.77 978.35,2047.24 643.23,2076.77 673.23,2076.77 703.23,2076.77 746.06,2106.3 825.55,2106.39 643.23,2106.77 673.23,2106.77 703.23,2106.77 905.28,2107.66
TS: J4.1 JP4.1 R3.1 R5.2 U1.16 | length 1096.9
  Top Layer w10: v1(981.42,2324.8) 981.42,2322.1 993.23,2310.29 993.23,2281.32 1000.92,2273.62 1011.87,2273.62
  Bottom Layer w10: J4.1@840.55,3031.5 979.13,3031.5 JP4.1@1005.91,3004.72 1070.08,3004.72 1098.43,2976.38 1098.43,2881.89 948.94,2732.4 R5.2@948.94,2365.16 R3.1@948.94,2324.8 v1(981.42,2324.8)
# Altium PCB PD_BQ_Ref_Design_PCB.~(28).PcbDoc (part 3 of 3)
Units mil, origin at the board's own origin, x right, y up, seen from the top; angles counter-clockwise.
Board outline 2300 x 3400 mil, 4 copper layers (Top Layer, Signal Layer 1, Signal Layer 2, Bottom Layer), stack 61.2 mil thick; 124 components, 53 nets, 359 pads, 494 vias.
Unrouted connection lines stored in the file: 227.

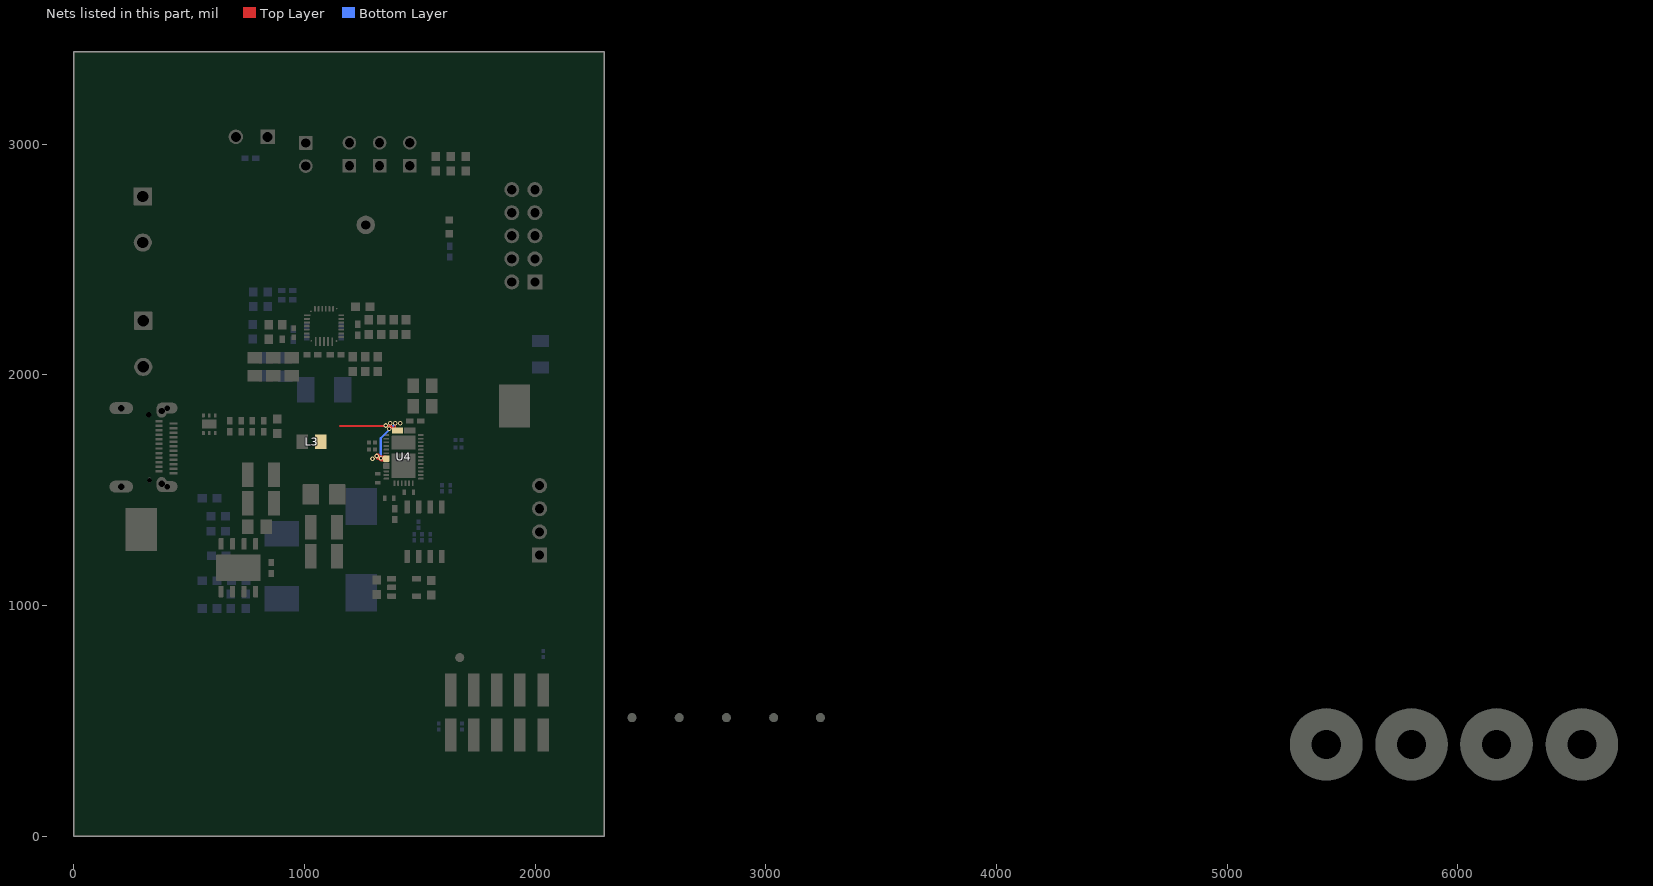
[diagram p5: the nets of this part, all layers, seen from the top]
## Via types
v1: diameter 20, hole 10, Top Layer to Bottom Layer, tented both sides, 445 vias
v2: diameter 23.62, hole 11.81, Top Layer to Bottom Layer, 24 vias
v3: diameter 30, hole 15, Top Layer to Bottom Layer, tented both sides, 12 vias
v4: diameter 19.68, hole 7.87, Top Layer to Bottom Layer, tented both sides, 10 vias
v5: diameter 20, hole 10, Top Layer to Bottom Layer, 3 vias

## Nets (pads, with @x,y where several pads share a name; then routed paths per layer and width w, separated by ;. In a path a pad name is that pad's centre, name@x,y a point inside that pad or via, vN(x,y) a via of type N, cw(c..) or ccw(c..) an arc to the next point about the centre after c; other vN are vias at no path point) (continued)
VBUS: L3.2 U4.23 U4.24 U4.25 U4.32 U4.33 U4.@1355.13,1636.01 U4.@1403.3,1758.05 | length 575.9
  Top Layer w6: v1@1330.71,1635.83 1354.95,1635.83 U4.@1355.13,1636.01 ; v1(1393.7,1789.37) 1393.7,1768.15 1403.54,1758.3 U4.@1403.3,1758.05
  Top Layer w10: 1155.51,1777.56 1352.36,1777.56 1372.91,1777.56 1392.41,1758.05 U4.@1403.3,1758.05
  Top Layer w20: v1@1340.55,1633.29 1333.24,1633.29 v1@1326.75,1639.79 ; U4.@1355.13,1636.01 1351.35,1639.79 v1@1326.75,1639.79 ; v1@1326.75,1639.79 1318.9,1647.64 v1(1312.99,1647.64) 1320.84,1639.79 v1@1326.75,1639.79
  Bottom Layer w10: v1@1330.71,1635.83 1330.71,1724.41 1393.7,1787.4 v1(1393.7,1789.37)
  other v1: 1295.28,1635.83 1331.68,1637.33 1368.11,1765.75 1352.36,1779.53 1372.05,1789.37 1415.35,1789.37
pads on no net: FID1.1 FID2.1 FID3.1 FID4.1 FID5.1 FID6.1 H1.1 H2.1 H3.1 H4.1 H5.0 H6.0 H7.0 H8.0 J3.1 J3.2 J3.3 J3.4 J3.7 J3.8 J5.4 J5.5 J5.6 J5.7 J5.8 J5.9 J6.A2 J6.A3 J6.A8 J6.A10 J6.A11 J6.ALIGN1 J6.ALIGN2 J6.B2 J6.B3 J6.B8 J6.B10 J6.B11 J7.1 SH-J1.0 SH-J2.0 U1.6 U1.7 U1.12 U1.21 U2.4 U3.9@713.58,1163.11 U4.6 U4.7 U4.13 U4.19 U4.36 U4.37 U6.7@569.88,1785.43 U6.7@605.31,1785.43

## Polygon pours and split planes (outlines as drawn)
NetC22_1 on Top Layer "TOP_LAYER_NETC22_1_P111" (solid, remove dead copper, pour order 111): 1034.7,2151.18 984.65,2151.18 984.25,2151.57 984.25,2122.05 1035.43,2122.05 1034.7,2122.78
STAT on Top Layer "TOP_LAYER_STAT_P109" (solid, remove dead copper, pour order 109): 1133.86,2151.18 1133.86,2125.4 1135.24,2124.02 1171.26,2124.02 1171.26,2151.12 1170.8,2151.57 1170.12,2150.9 1134.55,2150.9
PPHV on Top Layer "TOP_LAYER_PPHV_P107" (solid, remove dead copper, pour order 107): 1136.52,2270.16 1136.09,2270.59 1136.09,2314.96 1175.2,2335.59 1176.14,2334.65 1185.04,2334.65 1185.04,2322.83 1169.29,2307.09 1169.29,2255.91 1171.06,2254.14 1149.61,2254.14 1149.61,2267.72 1147.16,2270.16
TS on Top Layer "TOP_LAYER_TS_P105" (solid, remove dead copper, pour order 105): 988.19,2307.09 1021.54,2307.09 1033.46,2295.16 1033.46,2270.16 999.28,2270.16 999,2269.88 989.36,2279.53 988.19,2279.53
NetC1_2 on Top Layer "TOP_LAYER_NETC1_2_P103" (solid, remove dead copper, pour order 103): 1096.46,2208.66 1096.46,2167.32 1143.7,2167.32 1143.7,2208.66
NetC7_2 on Top Layer "TOP_LAYER_NETC7_2_P101" (solid, remove dead copper, pour order 101): 1029.53,2208.66 1029.53,2169.29 1072.83,2169.29 1072.83,2208.66
BAT on Top Layer "TOP_LAYER_BAT_P099" (solid, pour order 99): 905.51,2175.2 972.44,2175.2 972.44,2161.42 970.47,2159.45 905.51,2159.45 905.51,2174.96 905.28,2175.2
GND on Top Layer "tgaTOP_LAYER_GND_P081" (solid, pour order 97): 144.01,182.24 2144.01,182.24 2144.01,3182.24 144.01,3182.24
VBUS on Top Layer "Top Layer-VBUS" (solid, pour order 95): 1234.25,1773.62 1336.61,1773.62 1366.14,1744.09 1427.17,1744.09 1427.17,1838.58 1155.51,1838.58 1086.61,1769.69 1041.34,1769.69 1041.34,1643.7 1104.33,1643.7
NetC44_1 on Top Layer "Top Layer-NetC44_1" (solid, pour order 89): 562.99,1643.7 1021.65,1643.7 1021.65,1687.01 1021.65,1769.69 923.23,1769.69 635.83,1769.69 624.02,1757.87 551.18,1757.87 527.56,1734.25 460.63,1734.25 460.63,1625.98 545.28,1625.98
SYS on Top Layer "Top Layer-SYS" (solid, pour order 40): 677.17,1372.05 726.38,1322.83 726.38,1277.56 750,1277.56 781.5,1309.06 785.43,1309.06 785.43,1624.02 594.49,1624.02 594.49,1513.78 677.17,1513.78
NetC25_2 on Top Layer "Top Layer-NetC25_2" (solid, pour order 85): 822.83,1049.21 858.27,1049.21 907.48,1098.43 907.48,1153.54 822.83,1153.54
SYS on Top Layer "Top Layer-SYS 1" (solid, pour order 72): 391.73,2031.5 994.99,2031.5 1036.33,2072.83 1036.33,2120.08 687.01,2120.08 665.35,2141.73 433.07,2141.73 354.33,2220.47 354.33,2289.37 332.68,2289.37 248.03,2289.37 248.03,2175.2
LDO_1V5 on Top Layer "NONET_L-01_P-001" (solid, pour order 77): 1403.54,1517.72 1403.54,1541.34 1440.94,1541.34 1440.94,1478.35 1425.2,1478.35 1425.2,1496.06
AGND on Top Layer "NONET_L-01_P-001" (solid, pour order 76): 1537.4,2911.42 1734.25,2911.42 1734.25,2832.68 1537.4,2832.68
AGND on Top Layer "NONET_L-01_P-001" (solid, pour order 75): 1082.68,2273.62 1070.87,2273.62 1070.87,2334.65 1129.92,2334.65 1129.92,2273.62 1102.36,2273.62 1102.36,2301.18 1082.68,2301.18
BAT on Top Layer "Top Layer-BAT" (solid, pour order 66): 694.93,2131.84 785.43,2131.89 962.6,2131.89 990.16,2159.45 1019.69,2159.45 1019.69,2183.07 982.28,2183.07 962.6,2163.39 933.07,2163.39 921.26,2175.2 824.8,2175.2 657.48,2342.52 657.48,2425.2 441.48,2641.2 240.16,2641.2 240.16,2517.72 411.42,2517.72 549.21,2379.92 549.21,2277.56
PPHV on Top Layer "Top Layer-PPHV" (solid, pour order 51): 1405.51,1744.09 1482.28,1744.09 1482.28,1824.8 1513.78,1856.3 1513.78,2025.59 1513.78,2208.66 1179.13,2208.66 1179.13,2131.89 1368.11,2131.89 1405.51,2094.49
no net on Top Layer "NONET_L-01_P-001" (solid, pour order 49): 1513.78,2025.59
no net on Top Layer "NONET_L-01_P-001" (solid, pour order 48): 1513.78,2005.91
PPHV on Top Layer "NONET_L-01_P-001" (solid, pour order 14): 1226.81,2183.07 1252.24,2208.5 1460.53,2208.5 1460.7,2153.54 1148.74,2153.54 1148.74,2183.07
REGN on Top Layer "NONET_L-01_P-001" (solid, pour order 32): 1156.61,2206.69 1184.17,2206.69 1211.73,2234.25 1211.73,2246.06 1241.26,2275.59 1241.26,2312.99 1201.89,2312.99 1182.2,2293.31 1182.2,2224.41 1172.36,2214.57 1156.61,2214.57
PMID on Top Layer "NONET_L-01_P-001" (solid, pour order 42): 1134.96,2120.08 1368.11,2120.08 1368.11,2045.28 1162.52,2045.28 1134.96,2072.83
P3V3 on Top Layer "NONET_L-01_P-001" (solid, pour order 30): 1342.52,1553.15 1328.74,1539.37 1328.74,1523.62 1336.61,1523.62 1358.27,1545.28 1358.27,1553.15
VBUS on Top Layer "NONET_L-01_P-001" (solid, pour order 20): 1348.43,1622.05 1348.43,1649.61 1330.71,1649.61 1318.9,1661.42 1279.53,1661.42 1279.53,1622.05
LDO_1V5 on Top Layer "NONET_L-01_P-001" (solid, pour order 31): 1440.94,1468.5 1440.94,1533.46 1403.54,1533.46 1403.54,1517.72 1423.23,1517.72 1423.23,1468.5
LDO_3V3 on Top Layer "NONET_L-01_P-001" (solid, pour order 29): 1395.67,1525.59 1401.57,1519.69 1401.57,1466.54 1381.89,1466.54 1381.89,1494.09 1381.89,1525.59
PP5V on Top Layer "NONET_L-01_P-001" (solid, pour order 28): 1393.7,1529.53
PP5V on Top Layer "Top Layer-PP5V" (solid, pour order 17): 1100.39,1139.76 1240.16,1139.76 1240.16,1555.12 1275.59,1590.55 1368.11,1590.55 1368.11,1618.11 1287.4,1618.11 1267.53,1637.98 1169.47,1637.98 1147.64,1616.14 1100.39,1568.9
NetC1_2 on Bottom Layer "NONET_L-01_P-001" (solid, pour order 44): 1129.92,1881.89 1129.92,1986.22 1174.33,1986.22 1174.33,1881.89
NetC7_2 on Bottom Layer "NONET_L-01_P-001" (solid, pour order 43): 1043.31,1881.89 1043.31,1986.22 997.17,1986.22 997.16,1881.89
GND on Bottom Layer "BOTTOM_LAYER_GND_P090" (solid, remove dead copper, pour order 90): 120.15,186.87 2120.15,186.87 2120.15,3186.87 120.15,3186.87
SYS on Bottom Layer "Top Layer-SYS 1" (solid, pour order 87): 629.92,2031.5 994.99,2031.5 1036.33,2072.83 1036.33,2120.08 687.01,2120.08 665.35,2141.73 629.92,2141.73
SYS on Bottom Layer "Bottom Layer-SYS" (solid, pour order 74): 740.16,1726.38 740.16,1877.95 740.16,2122.05 629.92,2122.05 629.92,1828.74 629.92,1765.75 594.49,1730.32 594.49,1513.78 704.72,1513.78 704.72,1690.94
NetC25_2 on Bottom Layer "Bottom Layer-NetC25_2" (solid, pour order 84): 822.83,970.47 1090.55,970.47 1316.93,970.47 1316.93,1086.61 907.48,1086.61 907.48,1153.54 822.83,1153.54
NetU4_15 on Bottom Layer "NONET_L-01_P-001" (solid, pour order 78): 1377.76,1736.22 1377.76,1674.4 1481.97,1674.4 1482.29,1736.22
no net on Bottom Layer "NONET_L-01_P-001" (solid, pour order 37): 669.29,2216.54
PP5V on Bottom Layer "NONET_L-01_P-001" (solid, pour order 22): 1100.39,1509.84 1100.39,1291.34 1314.96,1291.34 1314.96,1509.84
VBUS on Bottom Layer "NONET_L-01_P-001" (solid, pour order 21): 1342.52,1622.05 1287.4,1622.05 1287.4,1736.22 1352.36,1801.18 1427.17,1801.18 1427.17,1744.09 1368.11,1744.09 1342.52,1718.5
AGND on Signal Layer 2 "SIGNAL_LAYER_2_AGND_P083" (solid, remove dead copper, pour order 83): 135.83,175.2 2135.83,175.2 2135.83,3175.2 135.83,3175.2
NetU4_15 on Signal Layer 2 "NONET_L-01_P-001" (solid, pour order 80): 1377.95,1734.86 1377.95,1675.2 1482.16,1675.38 1482.28,1734.86
NetC7_2 on Signal Layer 2 "NONET_L-01_P-001" (solid, pour order 45): 1030.63,2062.99 1003.07,2062.99 1003.07,2094.49 1030.63,2122.05 1030.63,2198.82 1071.97,2198.82 1071.97,2106.3
NetC1_2 on Signal Layer 2 "NONET_L-01_P-001" (solid, pour order 46): 1140.87,2062.99 1168.43,2062.99 1168.42,2094.49 1140.87,2122.05 1140.87,2198.82 1099.53,2198.82 1099.53,2106.3
GND on Signal Layer 1 "SIGNAL_LAYER_1_GND_P082" (solid, pour order 82): 135.83,175.2 2135.83,175.2 2135.83,3175.2 135.83,3175.2
NetU4_15 on Signal Layer 1 "NONET_L-01_P-001" (solid, pour order 79): 1377.95,1736.22 1482.28,1736.22 1481.9,1735.83 1481.9,1675.38 1377.96,1675.38

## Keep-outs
Keep-Out Layer:
  text ".Layer_Name" at 712.83,-683.3 h60

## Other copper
Top Layer:
  pour cut-out: 1135.83,1874.02 1135.83,1994.09 1035.43,1994.09 1035.43,1874.02
  text ".Layer_Name" at 712.83,-683.3 h60
Signal Layer 1:
  pour cut-out: 990.16,1996.06 1181.1,1996.06 1181.1,1874.02 992.13,1874.02
Signal Layer 2:
  pour cut-out: 990.16,2033.46 1181.1,2033.46 1181.1,1872.05 992.13,1872.05
Bottom Layer:
  pour cut-out: 990.16,1998.03 990.16,1872.05 1181.1,1872.05 1181.1,1998.03
  text ".Layer_Name" at 712.83,-683.3 h60

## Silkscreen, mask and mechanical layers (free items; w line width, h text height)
Top Overlay:
  lines w5: 522.64,1840.55 522.64,1948.82 522.64,2393.7 1373.03,2393.7 1627.95,2393.7 1627.95,940.94 522.64,940.94 522.64,1120.08 522.64,1843.5 ; 966.54,1870.08 982.28,1885.83 996.06,1899.61 996.06,2041.34 1009.84,2055.12 ; 1163.39,2055.12 1173.23,2045.28 1173.23,1899.61 1198.82,1874.02 1205.71,1867.13 ; 1250,2139.76 1263.78,2125.98 1377.95,2125.98 ; 1318.9,2273.62 1340.55,2295.28 ; 1350.39,2273.62 1374.02,2297.24 ; 1397.64,2273.62 1423.23,2299.21 ; 1450.79,2275.59 1476.38,2301.18 ; 1340.55,2295.28 1340.55,2295.28
  text "'.PRJ_Number'.PCB_Rev" at 1557.09,3057.09 h108.27
  text "up to 5A" at 181.1,2895.67 h60
  text "EXT_TS" at 678.26,2822.72 h60
  text "2S" at 1177.54,2805.26 h60
  text "4S" at 1442.04,2804.24 h60
  text "3S" at 1309.44,2803.65 h60
  text "TS" at 985.35,2798.34 h60
  text "GND" at 561.9,2703.85 h60 r90
  text "STAT" at 1432.2,2662.51 h60
  text "PPHV" at 1194.01,2489.28 h60
  text "BATT" at 573.71,2471.57 h60 r90
  text "up to 10A" at 188.98,2360.42 h60
  text "SYS" at 577.65,2186.13 h60 r90
  text "USB2ANY" at 1824.91,2083.77 h60
  text "Connector" at 1757.98,2029.64 h60
  text "GND" at 575.68,1979.44 h60 r90
  text "GND" at 1881.02,1638.89 h60
  text "GND" at 215.66,1102.47 h60
  text "Aardvark" at 1791.45,801.29 h60
  text "Connector" at 1757.98,741.25 h60
  text "Total Solution Size" at 527.67,723.54 h60
  text "USB-PD-CHG-EVM-01" at 493.83,503.94 h108
  text ".Layer_Name" at 712.83,-683.3 h60
Bottom Overlay:
  text ".Layer_Name" at 712.83,-683.3 h60
Top Paste:
  text ".Layer_Name" at 712.83,-683.3 h60
Bottom Paste:
  text ".Layer_Name" at 712.83,-683.3 h60
Top Solder:
  text ".Layer_Name" at 712.83,-683.3 h60
  text ".Layer_Name" at 712.83,-683.3 h60
Bottom Solder:
  text ".Layer_Name" at 712.83,-683.3 h60
Drill Guide:
  text ".Layer_Name" at 712.83,-683.3 h60
M1 Board Outline:
  lines w10: 135.83,175.2 135.83,3175.2 2135.83,3175.2 2135.83,175.2 135.83,175.2
  text ".Layer_Name" at 712.83,-683.3 h60
M2 Board Dimensions:
  rectangle: 135.83,-99.8 260.83,25.2
  rectangle: 260.83,-224.8 635.83,-99.8
  lines w7: 135.83,-99.8 1135.83,-99.8 ; 260.83,-224.8 260.83,25.2 ; 385.83,-224.8 385.83,25.2 ; 635.83,-224.8 635.83,25.2 ; 885.83,-224.8 885.83,25.2 ; 135.83,-224.8 1135.83,-224.8 1135.83,25.2 135.83,25.2 135.83,-224.8
  text ".Layer_Name" at 712.83,-683.3 h60
M3 3D STEP Top:
  text ".Layer_Name" at 712.83,-683.3 h60
M4 3D STEP Bottom:
  text ".Layer_Name" at 712.83,-683.3 h60
M5 Assembly Top:
  lines w10: -156.17,-754.97 6443.83,-754.97 ; -156.17,-551.64 6445.83,-551.64 ; -156.17,-348.3 -156.17,-958.3 3848.83,-958.3 6445.83,-958.3 6445.83,-348.3 -155.67,-348.3 -155.67,-958.3 1419.83,-958.3 ; 2308.83,-958.3 2308.83,-348.3 ; 3575.83,-551.64 3575.83,-348.3 ; 4415.83,-551.64 4415.83,-348.3 ; 5037.83,-964.8 5037.83,-761.97
  text "COMPONENTS MARKED 'DNP' SHOULD NOT BE POPULATED." at 1289.33,-143.3 h60
  text "ASSEMBLY VARIANT:" at 1288.83,-258.8 h60
  text ".VariantName" at 2324.83,-258.8 h60
  text "PCB VIEWED FROM TOP SIDE" at -92.67,-480.47 h60
  text "BOARD #:" at 2383.83,-480.47 h60
  text ".PRJ_Number" at 2929.33,-480.47 h60
  text "REV:" at 3773.83,-480.47 h60
  text ".PCB_Rev" at 4065.33,-480.47 h60
  text "SVN REV:" at 4611.83,-480.47 h60
  text ".VersionControl_RevNumber" at 5117.83,-480.47 h60
  text "TID #:" at 2383.83,-683.8 h60
  text ".TID" at 2929.33,-683.8 h60
  text "PLOT NAME =" at -92.67,-889.14 h60
  text ".plot_File_Name" at 712.83,-889.14 h60
  text "GENERATED    :" at 2385.83,-889.14 h60
  text ".Print_Date" at 3255.33,-889.14 h60
  text ".Print_Time" at 3984.33,-889.14 h60
  text "TEXAS INSTRUMENTS" at 5248.83,-889.14 h60
M6 Assembly Bottom:
  lines w10: -156.67,-552.14 6445.33,-552.14 ; -154.67,-755.47 6445.33,-755.47 ; 1251.33,-965.3 1251.33,-762.47 ; 1873.33,-552.14 1873.33,-348.8 ; 2713.33,-552.14 2713.33,-348.8 ; 3980.33,-958.8 3980.33,-348.8 ; 4869.33,-958.8 6444.83,-958.8 6444.83,-348.8 -156.67,-348.8 -156.67,-958.8 2440.33,-958.8 6445.33,-958.8 6445.33,-348.8
  text "COMPONENTS MARKED 'DNP' SHOULD NOT BE POPULATED." at 6237.83,-142.8 h60
  text ".VariantName" at 5193.83,-258.8 h60
  text "ASSEMBLY VARIANT:" at 6232.83,-258.8 h60
  text ".VersionControl_RevNumber" at 1171.33,-480.97 h60
  text "SVN REV:" at 1677.33,-480.97 h60
  text ".PCB_Rev" at 2223.83,-480.97 h60
  text "REV:" at 2515.33,-480.97 h60
  text ".PRJ_Number" at 3359.83,-480.97 h60
  text "BOARD #:" at 3905.33,-480.97 h60
  text "PCB VIEWED FROM BOTTOM SIDE" at 6381.83,-480.97 h60
  text ".TID" at 3359.83,-684.3 h60
  text "TID #:" at 3905.33,-684.3 h60
  text "TEXAS INSTRUMENTS" at 1040.33,-889.64 h60
  text ".Print_Time" at 2304.83,-889.64 h60
  text ".Print_Date" at 3033.83,-889.64 h60
  text "GENERATED    :" at 3903.33,-889.64 h60
  text ".plot_File_Name" at 5576.33,-889.64 h60
  text "PLOT NAME =" at 6381.83,-889.64 h60
M9 Title Sheet:
  drawing of 57 lines, arcs and shapes, not listed
  text "1" at 875.66,8211.7 h70
  text "2" at 3371.33,8211.7 h70
  text "3" at 5860.67,8211.7 h70
  text "4" at 8367.34,8211.7 h70
  text "5" at 10866.33,8211.7 h70
  text "6" at 13371.33,8211.7 h70
  text "A" at -280.67,7068.7 h70
  text "A" at 14519.33,7068.7 h70
  text "B" at -280.67,4688.7 h70
  text "B" at 14519.33,4688.7 h70
  text "C" at -280.67,2313.7 h70
  text "C" at 14519.33,2313.7 h70
  text "PROJECT TITLE:" at 11479.33,452.7 h45
  text ".PRJ_Title" at 11529.33,319.37 h70
  text "DESIGNED FOR:" at 11479.33,151.7 h45
  text ".PRJ_Customer" at 11529.33,11.7 h70
  text "D" at -280.67,-56.3 h70
  text "D" at 14519.33,-56.3 h70
  text "FILE NAME:" at 11479.33,-148.3 h45
  text ".PCB_File_Name_No_Path" at 11529.33,-268.3 h70
  text "Texas Instruments (TI) and/or its licensors do not warrant the accuracy or completeness of this specification" at 6509.83,-430.14 h45
  text "ENGINEER:" at 11479.33,-438.3 h45
  text "LAYOUT BY:" at 12984.33,-438.3 h45
  text "or any information contained therein. TI and/or its licensors do not warrant that this design will meet" at 6464.84,-542.81 h45
  text ".PRJ_Engineer" at 11529.33,-593.3 h70
  text ".PCB_Layout" at 13034.83,-593.3 h70
  text "the specifications, will be suitable for your application or fit for any particular purpose, or will operate in" at 6464.84,-655.47 h45
  text ".Layer_Name" at 712.83,-683.3 h60
  text "ALTIUM DESIGNER VERSION:" at 12984.33,-748.3 h45
  text "an implementation. TI and/or its licensors do not warrant that the design is production worthy. You should" at 6464.84,-768.14 h45
  text "completely validate and test your design implementation to confirm the system functionality for your application." at 6509.83,-880.8 h45
  text ".print_Scale" at 11529.33,-881.63 h70
  text ".Application_BuildNumber" at 13034.83,-881.63 h70
  text "1" at 875.66,-1088.3 h70
  text "2" at 3371.33,-1088.3 h70
  text "3" at 5860.67,-1088.3 h70
  text "4" at 8367.34,-1088.3 h70
  text "5" at 10866.33,-1088.3 h70
  text "6" at 13371.33,-1088.3 h70
M10 Fab Notes:
  drawing of 189 lines, arcs and shapes, not listed
  text "DESIGN INFORMATION" at 12517.84,6531.37 h60
  text "MIN. TRACK WIDTH:" at 11873.29,6399.24 h60
  text "8" at 12969.53,6399.25 h60
  text "MIL" at 13124.29,6399.24 h60
  text "MIN. CLEARANCE:" at 11873.29,6275.12 h60
  text "0.2" at 12909.53,6275.12 h60
  text "mm" at 13124.29,6275.12 h60
  text "MIN. VIA PAD SIZE:" at 11873.29,6150.99 h60
  text "24" at 12939.54,6151 h60
  text "MIL" at 13124.29,6150.99 h60
  text "0.05mm (2MIL)" at 12568.29,6021.09 h60
  text "MINIMUM ANNULAR RING" at 11544.05,6012.87 h60
  text "EXTERNAL" at 13276.29,6012.87 h60
  text "PER" at 11744.05,5902.74 h60
  text "IPC-D-275 CLASS 2 LEVEL C" at 11964.05,5902.74 h60
  text "MIL, HOLES" at 13452.29,5802.27 h60
  text "+/-" at 13059.83,5793.68 h60
  text "+/-" at 13913.83,5793.68 h60
  text "REGISTRATION TOLERANCES:" at 11544.05,5792.62 h60
  text "METAL" at 12743.83,5792.62 h60
  text "5" at 13320.03,5792.62 h60
  text "3" at 14153.03,5792.62 h60
  text "MIL" at 14269.29,5792.62 h60
  text "HOLE SIZE TOLERANCE (UNLESS OTHERWISE SPECIFIED):" at 11544.05,5694.3 h60
  text "+/-" at 13913.83,5691.43 h60
  text "3" at 14153.03,5690.37 h60
  text "MIL" at 14269.29,5690.36 h60
  text "MATERIAL:" at 11469.29,5552.72 h60
  text "FR-4 High Tg" at 12455.73,5424.19 h60
  text "X" at 12311.29,5416.2 h60
  text "FR-408" at 11890.29,5411.69 h60
  text "OTHER" at 13378.29,5411.69 h60
  text "62 MIL (1.6mm) +/-10%" at 12210.39,5268.66 h60
  text "X" at 12090.29,5266.2 h60
  text "THICKNESS:" at 11544.05,5260.43 h60
  text "OTHER" at 13495.29,5260.43 h60
  text "TOLERANCE:" at 11544.05,5122.12 h60
  text "X" at 12392.29,5122.12 h60
  text "ANSI IPC-6012 TYPE 3 CLASS 2" at 12570.3,5122.12 h60
  text "OTHER +/-" at 12570.29,4977.93 h60
  text "BOW & TWIST:" at 11544.05,4832.74 h60
  text "X" at 12392.29,4832.74 h60
  text "ANSI IPC-6012 TYPE 3 CLASS 2" at 12570.3,4832.74 h60
  text "OTHER +/-" at 12570.29,4686.05 h60
  text "DRILLING:" at 11469.29,4555.43 h60
  text "NC_DRILL FILES" at 13230.29,4450.24 h60
  text "REFERENCE:" at 11544.05,4446.3 h60
  text "X" at 12201.29,4446.2 h60
  text "AS SHOWN" at 12379.29,4446.3 h60
  text "X" at 13102.29,4446.3 h60
  text "OTHER" at 13528.29,4304.05 h60
  text "PTH COPPER THICKNESS:" at 11543.73,4300.52 h60
  text "X" at 12682.97,4300.52 h60
  text "20-30 um" at 12810.96,4300.52 h60
  text "BOARD FINISH:" at 11469.29,4152.92 h60
  text "SILKSCREEN:" at 11624.51,4042.8 h60
  text "X" at 12582.29,4042.8 h60
  text "TOP" at 12699.29,4042.8 h60
  text "X" at 13092.29,4042.8 h60
  text "BOTTOM" at 13210.29,4042.8 h60
  text "SILKSCREEN COLOR:" at 11624.51,3887.61 h60
  text "X" at 12581.29,3887.61 h60
  text "WHITE" at 12699.29,3887.61 h60
  text "OTHER" at 13210.29,3887.61 h60
  text "X" at 12712.29,3744.16 h60
  text "GREEN" at 12830.29,3744.16 h60
  text "OTHER" at 13448.29,3744.16 h60
  text "SOLDER RESIST COLOR:" at 11624.51,3737.29 h60
  text "X" at 12712.29,3589.91 h60
  text "MATTE" at 12830.29,3589.91 h60
  text "SEMI-GLOSS" at 13447.83,3589.27 h60
  text "IMMERSION GOLD (ENIG)" at 12530.29,3417.14 h60
  text "ENEPIG" at 13867.83,3409.91 h60
  text "SURFACE FINISH:" at 11469.29,3408.91 h60
  text "X" at 12352.29,3408.91 h60
  text "IMM. TIN/SILVER OR EQUIV" at 11798.83,3271.6 h60
  text "OTHER" at 13230.29,3267.66 h60
  text "ARRAY/PANEL:" at 11469.29,3112.28 h60
  text "CUT AND TRIM PER M1 BOARD OUTLINE" at 12530.29,3104.06 h60
  text "N.C. ROUTE" at 12530.29,2968.1 h60
  text "X" at 13218.29,2968.1 h60
  text "V. SCORE" at 13396.29,2968.1 h60
  text "CERTIFICATION:" at 11469.29,2838.97 h60
  text "MATERIALS AND WORKMANSHIP FOR ALL PCBS" at 12194.29,2838.97 h60
  text "TO MEET OR EXCEED THE REQUIREMENTS OF:" at 12194.29,2744.91 h60
  text "X" at 11831.8,2616.28 h60
  text "ANSI IPC-A-600F CLASS ->" at 11959.79,2616.28 h60
  text "X" at 13607.8,2616.28 h60
  text "2" at 13717.79,2616.28 h60
  text "1" at 13402.79,2614.78 h60
  text "3" at 14071.79,2614.78 h60
  text "X" at 12643.8,2468.59 h60
  text "RoHS" at 12771.79,2468.59 h60
  text "OTHER" at 13416.19,2468.59 h60
  text "PER ORDER" at 13813.25,2468.59 h60
  text "ALL BOARDS MUST MEET OR EXCEED UL94-V0 REQUIREMENTS." at 11496.83,2314.76 h60
  text "PCB MUST BEAR THE UL94V-0 UL REGISTERED MATERIAL ID NUMBER" at 11496.83,2198.7 h60
  text "ADDITIONAL REQUIREMENTS:" at 11469.29,2029.28 h60
  text "MICROSECTION:" at 11544.05,1922.15 h60
  text "YES" at 12449.79,1922.15 h60
  text "REQUIRED" at 13311.29,1777.82 h60
  text "BARE BOARD ELEC. TEST:" at 11544.05,1774.96 h60
  text "NONE" at 12849.79,1774.96 h60
  text "X" at 13193.29,1774.96 h60
  text "PER ORDER" at 13903.29,1774.96 h60
  text "XX MIL VIAS REQUIRE NON-CONDUCTIVE FILL AND PLANARIZE" at 11712.2,1570.01 h59
  text "XX MIL VIAS REQUIRE CONDUCTIVE FILL AND PLANARIZE" at 11720.2,1466.04 h60
  text "OUTER XX MIL TRACES REQUIRE 50 OHM SINGLE-ENDED IMPEDANCE" at 11719.22,1302.65 h58
  text "LAYER 2 & 3 (INNER LAYERS) XX MIL WIDE, XX MIL SPACE / TRACES REQUIRE 100 OHM DIFFERENTIAL IMPEDANCE" at 11711.22,1066.94 h60
  text ".Layer_Name" at 712.83,-683.3 h60
M11 Gerber Information:
  lines w10: -156.17,-754.97 6443.83,-754.97 ; -156.17,-551.64 6445.83,-551.64 ; -156.17,-348.3 -156.17,-958.3 3848.83,-958.3 6445.83,-958.3 6445.83,-348.3 -155.67,-348.3 -155.67,-958.3 1419.83,-958.3 ; 2308.83,-958.3 2308.83,-348.3 ; 3575.83,-551.64 3575.83,-348.3 ; 4415.83,-551.64 4415.83,-348.3 ; 5037.83,-964.8 5037.83,-761.97
  text "ALL ARTWORK VIEWED FROM TOP SIDE" at -92.67,-480.47 h60
  text "BOARD #:" at 2383.83,-480.47 h60
  text ".PRJ_Number" at 2929.33,-480.47 h60
  text "REV:" at 3773.83,-480.47 h60
  text ".PCB_Rev" at 4065.33,-480.47 h60
  text "SVN REV:" at 4611.83,-480.47 h60
  text ".VersionControl_RevNumber" at 5117.83,-480.47 h60
  text "LAYER NAME =" at -92.67,-683.3 h60
  text "TID #:" at 2383.83,-683.8 h60
  text ".TID" at 2929.33,-683.8 h60
  text "PLOT NAME =" at -92.67,-889.14 h60
  text ".plot_File_Name" at 712.83,-889.14 h60
  text "GENERATED    :" at 2385.83,-889.14 h60
  text ".Print_Date" at 3255.33,-889.14 h60
  text ".Print_Time" at 3984.33,-889.14 h60
  text "TEXAS INSTRUMENTS" at 5248.83,-889.14 h60
M12 Stackup:
  drawing of 295 lines, arcs and shapes, not listed
  text "Layer" at 9947.42,7802.64 h60
  text "Name" at 10357.33,7802.64 h60
  text "Material" at 11297.08,7802.64 h60
  text "Thickness" at 12156.84,7802.64 h60
  text "Constant" at 12806.68,7802.64 h60
  text "Board Layer Stack" at 13376.54,7802.64 h60
  text "1" at 9947.42,7682.64 h60
  text "Top Overlay" at 10357.33,7682.64 h60
  text "2" at 9947.42,7562.64 h60
  text "Top Solder" at 10357.33,7562.64 h60
  text "Solder Resist" at 11297.08,7562.64 h60
  text "0.40mil" at 12156.84,7562.64 h60
  text "3.5" at 12806.68,7562.64 h60
  text "3" at 9947.42,7442.64 h60
  text "Top Layer" at 10357.33,7442.64 h60
  text "Copper" at 11297.08,7442.64 h60
  text "2.80mil" at 12156.84,7442.64 h60
  text "4" at 9947.42,7322.64 h60
  text "Dielectric 1" at 10357.33,7322.64 h60
  text "FR-4 High TG" at 11297.08,7322.64 h60
  text "12.00mil" at 12156.84,7322.64 h60
  text "4.2" at 12806.68,7322.64 h60
  text "5" at 9947.42,7202.64 h60
  text "Signal Layer 1" at 10357.33,7202.64 h60
  text "Copper" at 11297.08,7202.64 h60
  text "2.80mil" at 12156.84,7202.64 h60
  text "6" at 9947.42,7082.64 h60
  text "Dielectric2" at 10357.33,7082.64 h60
  text "FR-4 High TG" at 11297.08,7082.64 h60
  text "26.00mil" at 12156.84,7082.64 h60
  text "4.2" at 12806.68,7082.64 h60
  text "7" at 9947.42,6962.64 h60
  text "Signal Layer 2" at 10357.33,6962.64 h60
  text "Copper" at 11297.08,6962.64 h60
  text "2.80mil" at 12156.84,6962.64 h60
  text "8" at 9947.42,6842.64 h60
  text "Dielectric3" at 10357.33,6842.64 h60
  text "FR-4 High TG" at 11297.08,6842.64 h60
  text "12.00mil" at 12156.84,6842.64 h60
  text "4.2" at 12806.68,6842.64 h60
  text "9" at 9947.42,6722.64 h60
  text "Bottom Layer" at 10357.33,6722.64 h60
  text "Copper" at 11297.08,6722.64 h60
  text "2.80mil" at 12156.84,6722.64 h60
  text "10" at 9947.42,6602.64 h60
  text "Bottom Solder" at 10357.33,6602.64 h60
  text "Solder Resist" at 11297.08,6602.64 h60
  text "0.40mil" at 12156.84,6602.64 h60
  text "3.5" at 12806.68,6602.64 h60
  text "11" at 9947.42,6482.64 h60
  text "Bottom Overlay" at 10357.33,6482.64 h60
  text ".Layer_Name" at 712.83,-683.3 h60
M13 Component Bodies Top:
  text ".Layer_Name" at 712.83,-683.3 h60
M14 Component Bodies Bottom:
  text ".Layer_Name" at 712.83,-683.3 h60
M15 Courtyards Top:
  text ".Layer_Name" at 712.83,-683.3 h60
M16 Courtyards Bottom:
  text ".Layer_Name" at 712.83,-683.3 h60
Drill Drawing:
  drawing of 152 lines, arcs and shapes, not listed
  text "Symbol" at 5496.42,3681.15 h72
  text "Quantity" at 5796.98,3681.15 h72
  text "Finished Hole Size" at 6128.99,3681.15 h72
  text "Plated" at 6765.55,3681.15 h72
  text "Hole Type" at 7024.69,3681.15 h72
  text "Drill Layer Pair" at 7399.85,3681.15 h72
  text "Hole Tolerance" at 8124.18,3681.15 h72
  text "1" at 5796.98,3556.83 h60
  text "23.62mil (0.600mm)" at 6128.99,3556.83 h60
  text "NPTH" at 6765.55,3556.83 h60
  text "Round" at 7024.69,3556.83 h60
  text "Top Layer - Bottom Layer" at 7399.85,3556.83 h60
  text "+/-1.18mil" at 8124.18,3556.83 h60
  text "10" at 5796.98,3432.51 h60
  text "7.87mil (0.200mm)" at 6128.99,3432.51 h60
  text "PTH" at 6765.55,3432.51 h60
  text "Round" at 7024.69,3432.51 h60
  text "Top Layer - Bottom Layer" at 7399.85,3432.51 h60
  text "448" at 5796.98,3308.19 h60
  text "10.00mil (0.254mm)" at 6128.99,3308.19 h60
  text "PTH" at 6765.55,3308.19 h60
  text "Round" at 7024.69,3308.19 h60
  text "Top Layer - Bottom Layer" at 7399.85,3308.19 h60
  text "24" at 5796.98,3183.87 h60
  text "11.81mil (0.300mm)" at 6128.99,3183.87 h60
  text "PTH" at 6765.55,3183.87 h60
  text "Round" at 7024.69,3183.87 h60
  text "Top Layer - Bottom Layer" at 7399.85,3183.87 h60
  text "12" at 5796.98,3059.55 h60
  text "15.00mil (0.381mm)" at 6128.99,3059.55 h60
  text "PTH" at 6765.55,3059.55 h60
  text "Round" at 7024.69,3059.55 h60
  text "Top Layer - Bottom Layer" at 7399.85,3059.55 h60
  text "4" at 5796.98,2935.23 h60
  text "39.37mil (1.000mm)" at 6128.99,2935.23 h60
  text "PTH" at 6765.55,2935.23 h60
  text "Round" at 7024.69,2935.23 h60
  text "Top Layer - Bottom Layer" at 7399.85,2935.23 h60
  text "19" at 5796.98,2810.91 h60
  text "40.00mil (1.016mm)" at 6128.99,2810.91 h60
  text "PTH" at 6765.55,2810.91 h60
  text "Round" at 7024.69,2810.91 h60
  text "Top Layer - Bottom Layer" at 7399.85,2810.91 h60
  text "2" at 5796.98,2686.59 h60
  text "43.31mil (1.100mm)" at 6128.99,2686.59 h60
  text "PTH" at 6765.55,2686.59 h60
  text "Round" at 7024.69,2686.59 h60
  text "Top Layer - Bottom Layer" at 7399.85,2686.59 h60
  text "4" at 5796.98,2562.27 h60
  text "49.21mil (1.250mm)" at 6128.99,2562.27 h60
  text "PTH" at 6765.55,2562.27 h60
  text "Round" at 7024.69,2562.27 h60
  text "Top Layer - Bottom Layer" at 7399.85,2562.27 h60
  text "4" at 5796.98,2437.95 h60
  text "125.98mil (3.200mm)" at 6128.99,2437.95 h60
  text "PTH" at 6765.55,2437.95 h60
  text "Round" at 7024.69,2437.95 h60
  text "Top Layer - Bottom Layer" at 7399.85,2437.95 h60
  text "1" at 5796.98,2313.63 h60
  text "19.69mil (0.500mm)" at 6128.99,2313.63 h60
  text "NPTH" at 6765.55,2313.63 h60
  text "Slot" at 7024.69,2313.63 h60
  text "Top Layer - Bottom Layer" at 7399.85,2313.63 h60
  text "+/-1.18mil" at 8124.18,2313.63 h60
  text "2" at 5796.98,2189.31 h60
  text "23.62mil (0.600mm)" at 6128.99,2189.31 h60
  text "PTH" at 6765.55,2189.31 h60
  text "Slot" at 7024.69,2189.31 h60
  text "Top Layer - Bottom Layer" at 7399.85,2189.31 h60
  text "+/-1.97mil" at 8124.18,2189.31 h60
  text "2" at 5796.98,2064.99 h60
  text "27.56mil (0.700mm)" at 6128.99,2064.99 h60
  text "PTH" at 6765.55,2064.99 h60
  text "Slot" at 7024.69,2064.99 h60
  text "Top Layer - Bottom Layer" at 7399.85,2064.99 h60
  text "+/-1.97mil" at 8124.18,2064.99 h60
  text "2" at 5796.98,1940.67 h60
  text "27.56mil (0.700mm)" at 6128.99,1940.67 h60
  text "PTH" at 6765.55,1940.67 h60
  text "Slot" at 7024.69,1940.67 h60
  text "Top Layer - Bottom Layer" at 7399.85,1940.67 h60
  text "+/-1.97mil" at 8124.18,1940.67 h60
  text "535 Total" at 5796.98,1816.35 h60
  text "Slot definitions :" at 5496.42,1729.33 h60
  text "Routed Path Length" at 5947.13,1729.33 h60
  text "= Calculated from tool start centre position to tool end centre position." at 6486.87,1729.33 h60
  text "Hole Length" at 5947.13,1679.6 h60
  text "= Routed Path Length + Tool Size = Slot length as defined in the PCB layout" at 6287.07,1679.6 h60
  text ".Layer_Name" at 712.83,-683.3 h60
M17 Embedded Cavity:
  text ".Layer_Name" at 712.83,-683.3 h60
M18 Embedded Assembly:
  text ".Layer_Name" at 712.83,-683.3 h60
M19 Embedded Keepout:
  text ".Layer_Name" at 712.83,-683.3 h60

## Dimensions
1627.95,2393.7 to 1627.95,940.94 on Top Overlay
522.64,940.94 to 1627.95,940.94 on Top Overlay
135.83,-224.8 to 1135.83,-224.8 on M2 Board Dimensions
135.83,175.2 to 0.39,3400 on M2 Board Dimensions
135.83,175.2 to 2300,0 on M2 Board Dimensions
